VERSION 5.8 ;
BUSBITCHARS "[]" ;
DIVIDERCHAR "/" ;
CLEARANCEMEASURE EUCLIDEAN ;

SITE coresite_DH_P
    SIZE 0.0450 BY 0.2880 ;
    CLASS CORE ;
    SYMMETRY X Y ;
END coresite_DH_P

SITE coresite_DH_N
    SIZE 0.0450 BY 0.2880 ;
    CLASS CORE ;
    SYMMETRY X Y ;
END coresite_DH_N

SITE coresite
    SIZE 0.0450 BY 0.1440 ;
    CLASS CORE ;
    SYMMETRY X Y ;
END coresite

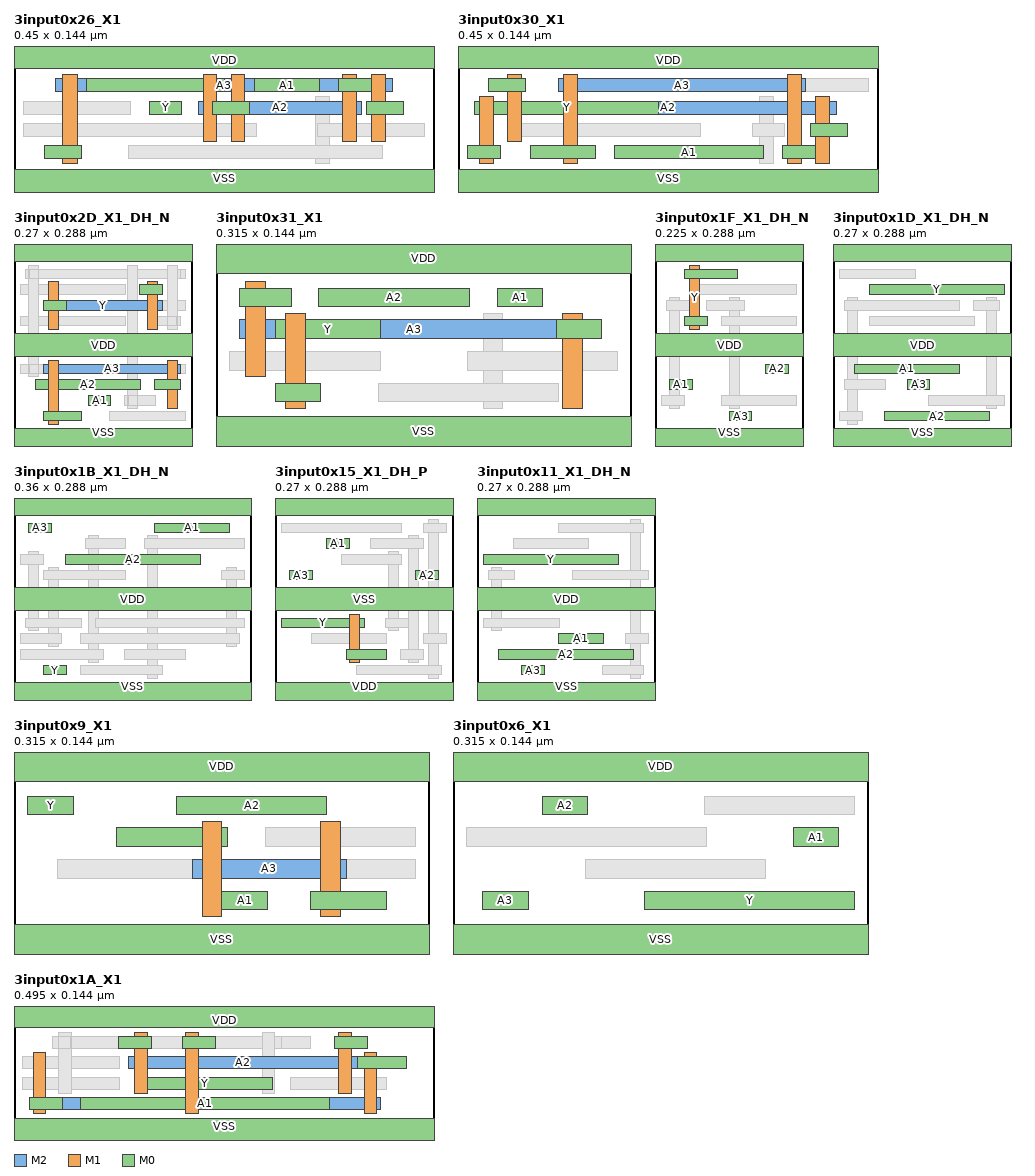
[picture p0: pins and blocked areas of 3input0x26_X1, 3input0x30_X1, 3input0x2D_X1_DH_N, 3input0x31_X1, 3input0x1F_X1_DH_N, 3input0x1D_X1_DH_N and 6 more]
MACRO 3input0x26_X1
  CLASS CORE ;
  ORIGIN 0 0 ;
  FOREIGN 3input0x26_X1 0 0 ;
  SIZE 0.4500 BY 0.1440 ;
  SYMMETRY X Y ;
  SITE coresite ;
  PIN A2
    DIRECTION INPUT ;
    USE SIGNAL ;
    PORT
      LAYER M2 ;
        RECT 0.1980 0.0910 0.3720 0.0770 ;
      LAYER M1 ;
        RECT 0.2025 0.1200 0.2175 0.0480 ;
        RECT 0.3525 0.1200 0.3675 0.0480 ;
      LAYER M0 ;
        RECT 0.0780 0.1150 0.2250 0.1010 ;
        RECT 0.3480 0.1150 0.3825 0.1010 ;
    END
  END A2
  PIN A3
    DIRECTION INPUT ;
    USE SIGNAL ;
    PORT
      LAYER M2 ;
        RECT 0.0450 0.1150 0.4050 0.1010 ;
      LAYER M1 ;
        RECT 0.0525 0.1200 0.0675 0.0240 ;
        RECT 0.2325 0.1200 0.2475 0.0480 ;
        RECT 0.3825 0.1200 0.3975 0.0480 ;
      LAYER M0 ;
        RECT 0.0330 0.0430 0.0720 0.0290 ;
        RECT 0.2130 0.0910 0.2520 0.0770 ;
        RECT 0.3780 0.0910 0.4170 0.0770 ;
    END
  END A3
  PIN Y
    DIRECTION OUTPUT ;
    USE SIGNAL ;
    PORT
      LAYER M0 ;
        RECT 0.1455 0.0910 0.1800 0.0770 ;
    END
  END Y
  PIN A1
    DIRECTION INPUT ;
    USE SIGNAL ;
    PORT
      LAYER M0 ;
        RECT 0.2580 0.1150 0.3270 0.1010 ;
    END
  END A1
  PIN VDD
    DIRECTION INOUT ;
    USE POWER ;
    SHAPE ABUTMENT ;
    PORT
      LAYER M0 ;
        RECT 0.0000 0.1260 0.4500 0.1620 ;
    END
  END VDD
  PIN VSS
    DIRECTION INOUT ;
    USE GROUND ;
    SHAPE ABUTMENT ;
    PORT
      LAYER M0 ;
        RECT 0.0000 -0.0180 0.4500 0.0180 ;
    END
  END VSS
  OBS
      LAYER V0 ;
        RECT 0.0530 0.0290 0.0670 0.0430 ;
        RECT 0.2330 0.0770 0.2470 0.0910 ;
        RECT 0.3830 0.0770 0.3970 0.0910 ;
        RECT 0.2030 0.1010 0.2170 0.1150 ;
        RECT 0.3530 0.1010 0.3670 0.1150 ;
        RECT 0.3230 0.0770 0.3370 0.0910 ;
        RECT 0.3230 0.0290 0.3370 0.0430 ;
      LAYER M1 ;
        RECT 0.3225 0.0960 0.3375 0.0240 ;
      LAYER M0 ;
        RECT 0.1230 0.0290 0.3945 0.0430 ;
        RECT 0.0105 0.0530 0.2595 0.0670 ;
        RECT 0.3255 0.0530 0.4395 0.0670 ;
        RECT 0.0105 0.0770 0.1245 0.0910 ;
        RECT 0.3150 0.0770 0.3495 0.0910 ;
      LAYER V1 ;
        RECT 0.0530 0.1010 0.0670 0.1150 ;
        RECT 0.2330 0.1010 0.2470 0.1150 ;
        RECT 0.3830 0.1010 0.3970 0.1150 ;
        RECT 0.2030 0.0770 0.2170 0.0910 ;
        RECT 0.3530 0.0770 0.3670 0.0910 ;
  END
END 3input0x26_X1

MACRO 3input0x30_X1
  CLASS CORE ;
  ORIGIN 0 0 ;
  FOREIGN 3input0x30_X1 0 0 ;
  SIZE 0.4500 BY 0.1440 ;
  SYMMETRY X Y ;
  SITE coresite ;
  PIN Y
    DIRECTION OUTPUT ;
    USE SIGNAL ;
    PORT
      LAYER M1 ;
        RECT 0.0225 0.0960 0.0375 0.0240 ;
      LAYER M0 ;
        RECT 0.0105 0.0430 0.0450 0.0290 ;
        RECT 0.0180 0.0910 0.2145 0.0770 ;
    END
  END Y
  PIN A2
    DIRECTION INPUT ;
    USE SIGNAL ;
    PORT
      LAYER M2 ;
        RECT 0.0450 0.0910 0.4050 0.0770 ;
      LAYER M1 ;
        RECT 0.3825 0.0960 0.3975 0.0240 ;
        RECT 0.0525 0.1200 0.0675 0.0480 ;
      LAYER M0 ;
        RECT 0.3780 0.0670 0.4170 0.0530 ;
        RECT 0.0330 0.1150 0.0720 0.1010 ;
    END
  END A2
  PIN A3
    DIRECTION INPUT ;
    USE SIGNAL ;
    PORT
      LAYER M2 ;
        RECT 0.1080 0.1150 0.3720 0.1010 ;
      LAYER M1 ;
        RECT 0.1125 0.1200 0.1275 0.0240 ;
        RECT 0.3525 0.1200 0.3675 0.0240 ;
      LAYER M0 ;
        RECT 0.0780 0.0430 0.1470 0.0290 ;
        RECT 0.3480 0.0430 0.3825 0.0290 ;
    END
  END A3
  PIN A1
    DIRECTION INPUT ;
    USE SIGNAL ;
    PORT
      LAYER M0 ;
        RECT 0.1680 0.0430 0.3270 0.0290 ;
    END
  END A1
  PIN VDD
    DIRECTION INOUT ;
    USE POWER ;
    SHAPE ABUTMENT ;
    PORT
      LAYER M0 ;
        RECT 0.0000 0.1260 0.4500 0.1620 ;
    END
  END VDD
  PIN VSS
    DIRECTION INOUT ;
    USE GROUND ;
    SHAPE ABUTMENT ;
    PORT
      LAYER M0 ;
        RECT 0.0000 -0.0180 0.4500 0.0180 ;
    END
  END VSS
  OBS
      LAYER V0 ;
        RECT 0.0530 0.1010 0.0670 0.1150 ;
        RECT 0.3830 0.0530 0.3970 0.0670 ;
        RECT 0.3230 0.0770 0.3370 0.0910 ;
        RECT 0.3230 0.0530 0.3370 0.0670 ;
        RECT 0.1130 0.0290 0.1270 0.0430 ;
        RECT 0.3530 0.0290 0.3670 0.0430 ;
        RECT 0.0230 0.0770 0.0370 0.0910 ;
        RECT 0.0230 0.0290 0.0370 0.0430 ;
      LAYER M1 ;
        RECT 0.3225 0.0960 0.3375 0.0240 ;
      LAYER M0 ;
        RECT 0.0555 0.0530 0.2595 0.0670 ;
        RECT 0.3150 0.0530 0.3495 0.0670 ;
        RECT 0.2580 0.0770 0.3945 0.0910 ;
        RECT 0.1455 0.1010 0.2595 0.1150 ;
        RECT 0.3255 0.1010 0.4395 0.1150 ;
      LAYER V1 ;
        RECT 0.0530 0.0770 0.0670 0.0910 ;
        RECT 0.3830 0.0770 0.3970 0.0910 ;
        RECT 0.1130 0.1010 0.1270 0.1150 ;
        RECT 0.3530 0.1010 0.3670 0.1150 ;
  END
END 3input0x30_X1

MACRO 3input0x2D_X1_DH_N
  CLASS CORE ;
  ORIGIN 0 0 ;
  FOREIGN 3input0x2D_X1_DH_N 0 0 ;
  SIZE 0.2700 BY 0.2880 ;
  SYMMETRY X Y ;
  SITE coresite_DH_N ;
  PIN A3
    DIRECTION INPUT ;
    USE SIGNAL ;
    PORT
      LAYER M2 ;
        RECT 0.0450 0.1150 0.2520 0.1010 ;
      LAYER M1 ;
        RECT 0.0525 0.1200 0.0675 0.0240 ;
        RECT 0.2325 0.1200 0.2475 0.0480 ;
      LAYER M0 ;
        RECT 0.0450 0.0430 0.1020 0.0290 ;
        RECT 0.2130 0.0910 0.2520 0.0770 ;
    END
  END A3
  PIN Y
    DIRECTION OUTPUT ;
    USE SIGNAL ;
    PORT
      LAYER M2 ;
        RECT 0.0450 0.2110 0.2250 0.1970 ;
      LAYER M1 ;
        RECT 0.0525 0.2400 0.0675 0.1680 ;
        RECT 0.2025 0.2400 0.2175 0.1680 ;
      LAYER M0 ;
        RECT 0.0450 0.2110 0.0795 0.1970 ;
        RECT 0.1905 0.2350 0.2250 0.2210 ;
    END
  END Y
  PIN A1
    DIRECTION INPUT ;
    USE SIGNAL ;
    PORT
      LAYER M0 ;
        RECT 0.1125 0.0670 0.1470 0.0530 ;
    END
  END A1
  PIN A2
    DIRECTION INPUT ;
    USE SIGNAL ;
    PORT
      LAYER M0 ;
        RECT 0.0330 0.0910 0.1920 0.0770 ;
    END
  END A2
  PIN VDD
    DIRECTION INOUT ;
    USE POWER ;
    SHAPE ABUTMENT ;
    PORT
      LAYER M0 ;
        RECT 0.0000 0.1260 0.2700 0.1620 ;
    END
  END VDD
  PIN VSS
    DIRECTION INOUT ;
    USE GROUND ;
    SHAPE ABUTMENT ;
    PORT
      LAYER M0 ;
        RECT 0.0000 -0.0180 0.2700 0.0180 ;
        RECT 0.0000 0.2700 0.2700 0.3060 ;
    END
  END VSS
  OBS
      LAYER V1 ;
        RECT 0.2330 0.2450 0.2470 0.2590 ;
        RECT 0.0230 0.2450 0.0370 0.2590 ;
        RECT 0.1730 0.2450 0.1870 0.2590 ;
        RECT 0.0530 0.1010 0.0670 0.1150 ;
        RECT 0.2330 0.1010 0.2470 0.1150 ;
        RECT 0.0530 0.1970 0.0670 0.2110 ;
        RECT 0.2030 0.1970 0.2170 0.2110 ;
      LAYER M0 ;
        RECT 0.1455 0.0290 0.2595 0.0430 ;
        RECT 0.1680 0.0530 0.2145 0.0670 ;
        RECT 0.0105 0.1010 0.0450 0.1150 ;
        RECT 0.1455 0.1010 0.2595 0.1150 ;
        RECT 0.0105 0.1730 0.1695 0.1870 ;
        RECT 0.2130 0.1730 0.2520 0.1870 ;
        RECT 0.1005 0.1970 0.2595 0.2110 ;
        RECT 0.0105 0.2210 0.1695 0.2350 ;
        RECT 0.0180 0.2450 0.0570 0.2590 ;
        RECT 0.1005 0.2450 0.2595 0.2590 ;
      LAYER M2 ;
        RECT 0.0180 0.2450 0.2520 0.2590 ;
      LAYER M1 ;
        RECT 0.0225 0.2640 0.0375 0.0960 ;
        RECT 0.1725 0.2640 0.1875 0.0480 ;
        RECT 0.2325 0.2640 0.2475 0.1680 ;
      LAYER V0 ;
        RECT 0.2330 0.1730 0.2470 0.1870 ;
        RECT 0.0230 0.1010 0.0370 0.1150 ;
        RECT 0.0230 0.2450 0.0370 0.2590 ;
        RECT 0.1730 0.0530 0.1870 0.0670 ;
        RECT 0.0530 0.0290 0.0670 0.0430 ;
        RECT 0.2330 0.0770 0.2470 0.0910 ;
        RECT 0.0530 0.1970 0.0670 0.2110 ;
        RECT 0.2030 0.2210 0.2170 0.2350 ;
  END
END 3input0x2D_X1_DH_N

MACRO 3input0x31_X1
  CLASS CORE ;
  ORIGIN 0 0 ;
  FOREIGN 3input0x31_X1 0 0 ;
  SIZE 0.3150 BY 0.1440 ;
  SYMMETRY X Y ;
  SITE coresite ;
  PIN Y
    DIRECTION OUTPUT ;
    USE SIGNAL ;
    PORT
      LAYER M1 ;
        RECT 0.0525 0.0960 0.0675 0.0240 ;
      LAYER M0 ;
        RECT 0.0450 0.0430 0.0795 0.0290 ;
        RECT 0.0450 0.0910 0.1245 0.0770 ;
    END
  END Y
  PIN A3
    DIRECTION INPUT ;
    USE SIGNAL ;
    PORT
      LAYER M2 ;
        RECT 0.0180 0.0910 0.2820 0.0770 ;
      LAYER M1 ;
        RECT 0.2625 0.0960 0.2775 0.0240 ;
        RECT 0.0225 0.1200 0.0375 0.0480 ;
      LAYER M0 ;
        RECT 0.2580 0.0910 0.2925 0.0770 ;
        RECT 0.0180 0.1150 0.0570 0.1010 ;
    END
  END A3
  PIN A2
    DIRECTION INPUT ;
    USE SIGNAL ;
    PORT
      LAYER M0 ;
        RECT 0.0780 0.1150 0.1920 0.1010 ;
    END
  END A2
  PIN A1
    DIRECTION INPUT ;
    USE SIGNAL ;
    PORT
      LAYER M0 ;
        RECT 0.2130 0.1150 0.2475 0.1010 ;
    END
  END A1
  PIN VDD
    DIRECTION INOUT ;
    USE POWER ;
    SHAPE ABUTMENT ;
    PORT
      LAYER M0 ;
        RECT 0.0000 0.1260 0.3150 0.1620 ;
    END
  END VDD
  PIN VSS
    DIRECTION INOUT ;
    USE GROUND ;
    SHAPE ABUTMENT ;
    PORT
      LAYER M0 ;
        RECT 0.0000 -0.0180 0.3150 0.0180 ;
    END
  END VSS
  OBS
      LAYER V0 ;
        RECT 0.0530 0.0770 0.0670 0.0910 ;
        RECT 0.0530 0.0290 0.0670 0.0430 ;
        RECT 0.2030 0.0770 0.2170 0.0910 ;
        RECT 0.2030 0.0290 0.2170 0.0430 ;
        RECT 0.0230 0.1010 0.0370 0.1150 ;
        RECT 0.2630 0.0770 0.2770 0.0910 ;
      LAYER M1 ;
        RECT 0.2025 0.0960 0.2175 0.0240 ;
      LAYER M0 ;
        RECT 0.1230 0.0290 0.2595 0.0430 ;
        RECT 0.0105 0.0530 0.1245 0.0670 ;
        RECT 0.1905 0.0530 0.3045 0.0670 ;
        RECT 0.1905 0.0770 0.2250 0.0910 ;
      LAYER V1 ;
        RECT 0.0230 0.0770 0.0370 0.0910 ;
        RECT 0.2630 0.0770 0.2770 0.0910 ;
  END
END 3input0x31_X1

MACRO 3input0x1F_X1_DH_N
  CLASS CORE ;
  ORIGIN 0 0 ;
  FOREIGN 3input0x1F_X1_DH_N 0 0 ;
  SIZE 0.2250 BY 0.2880 ;
  SYMMETRY X Y ;
  SITE coresite_DH_N ;
  PIN Y
    DIRECTION OUTPUT ;
    USE SIGNAL ;
    PORT
      LAYER M1 ;
        RECT 0.0525 0.2640 0.0675 0.1680 ;
      LAYER M0 ;
        RECT 0.0450 0.1870 0.0795 0.1730 ;
        RECT 0.0450 0.2590 0.1245 0.2450 ;
    END
  END Y
  PIN A3
    DIRECTION INPUT ;
    USE SIGNAL ;
    PORT
      LAYER M0 ;
        RECT 0.1125 0.0430 0.1470 0.0290 ;
    END
  END A3
  PIN A1
    DIRECTION INPUT ;
    USE SIGNAL ;
    PORT
      LAYER M0 ;
        RECT 0.0225 0.0910 0.0570 0.0770 ;
    END
  END A1
  PIN A2
    DIRECTION INPUT ;
    USE SIGNAL ;
    PORT
      LAYER M0 ;
        RECT 0.1680 0.1150 0.2025 0.1010 ;
    END
  END A2
  PIN VDD
    DIRECTION INOUT ;
    USE POWER ;
    SHAPE ABUTMENT ;
    PORT
      LAYER M0 ;
        RECT 0.0000 0.1260 0.2250 0.1620 ;
    END
  END VDD
  PIN VSS
    DIRECTION INOUT ;
    USE GROUND ;
    SHAPE ABUTMENT ;
    PORT
      LAYER M0 ;
        RECT 0.0000 -0.0180 0.2250 0.0180 ;
        RECT 0.0000 0.2700 0.2250 0.3060 ;
    END
  END VSS
  OBS
      LAYER V0 ;
        RECT 0.0230 0.0530 0.0370 0.0670 ;
        RECT 0.0230 0.1970 0.0370 0.2110 ;
        RECT 0.0530 0.2450 0.0670 0.2590 ;
        RECT 0.0530 0.1730 0.0670 0.1870 ;
        RECT 0.1130 0.0530 0.1270 0.0670 ;
        RECT 0.1130 0.1970 0.1270 0.2110 ;
      LAYER M1 ;
        RECT 0.0225 0.2160 0.0375 0.0480 ;
        RECT 0.1125 0.2160 0.1275 0.0480 ;
      LAYER M0 ;
        RECT 0.0105 0.0530 0.0450 0.0670 ;
        RECT 0.1005 0.0530 0.2145 0.0670 ;
        RECT 0.1005 0.1730 0.2145 0.1870 ;
        RECT 0.0180 0.1970 0.0570 0.2110 ;
        RECT 0.0780 0.1970 0.1350 0.2110 ;
        RECT 0.0555 0.2210 0.2145 0.2350 ;
  END
END 3input0x1F_X1_DH_N

MACRO 3input0x1D_X1_DH_N
  CLASS CORE ;
  ORIGIN 0 0 ;
  FOREIGN 3input0x1D_X1_DH_N 0 0 ;
  SIZE 0.2700 BY 0.2880 ;
  SYMMETRY X Y ;
  SITE coresite_DH_N ;
  PIN A2
    DIRECTION INPUT ;
    USE SIGNAL ;
    PORT
      LAYER M0 ;
        RECT 0.0780 0.0430 0.2370 0.0290 ;
    END
  END A2
  PIN A3
    DIRECTION INPUT ;
    USE SIGNAL ;
    PORT
      LAYER M0 ;
        RECT 0.1125 0.0910 0.1470 0.0770 ;
    END
  END A3
  PIN A1
    DIRECTION INPUT ;
    USE SIGNAL ;
    PORT
      LAYER M0 ;
        RECT 0.0330 0.1150 0.1920 0.1010 ;
    END
  END A1
  PIN Y
    DIRECTION OUTPUT ;
    USE SIGNAL ;
    PORT
      LAYER M0 ;
        RECT 0.0555 0.2350 0.2595 0.2210 ;
    END
  END Y
  PIN VDD
    DIRECTION INOUT ;
    USE POWER ;
    SHAPE ABUTMENT ;
    PORT
      LAYER M0 ;
        RECT 0.0000 0.1260 0.2700 0.1620 ;
    END
  END VDD
  PIN VSS
    DIRECTION INOUT ;
    USE GROUND ;
    SHAPE ABUTMENT ;
    PORT
      LAYER M0 ;
        RECT 0.0000 -0.0180 0.2700 0.0180 ;
        RECT 0.0000 0.2700 0.2700 0.3060 ;
    END
  END VSS
  OBS
      LAYER V0 ;
        RECT 0.2330 0.0530 0.2470 0.0670 ;
        RECT 0.2330 0.1970 0.2470 0.2110 ;
        RECT 0.0230 0.0770 0.0370 0.0910 ;
        RECT 0.0230 0.0290 0.0370 0.0430 ;
        RECT 0.0230 0.1970 0.0370 0.2110 ;
      LAYER M1 ;
        RECT 0.0225 0.2160 0.0375 0.0240 ;
        RECT 0.2325 0.2160 0.2475 0.0480 ;
      LAYER M0 ;
        RECT 0.0105 0.0290 0.0450 0.0430 ;
        RECT 0.1455 0.0530 0.2595 0.0670 ;
        RECT 0.0180 0.0770 0.0795 0.0910 ;
        RECT 0.0555 0.1730 0.2145 0.1870 ;
        RECT 0.0180 0.1970 0.1920 0.2110 ;
        RECT 0.2130 0.1970 0.2520 0.2110 ;
        RECT 0.0105 0.2450 0.1245 0.2590 ;
  END
END 3input0x1D_X1_DH_N

MACRO 3input0x1B_X1_DH_N
  CLASS CORE ;
  ORIGIN 0 0 ;
  FOREIGN 3input0x1B_X1_DH_N 0 0 ;
  SIZE 0.3600 BY 0.2880 ;
  SYMMETRY X Y ;
  SITE coresite_DH_N ;
  PIN Y
    DIRECTION OUTPUT ;
    USE SIGNAL ;
    PORT
      LAYER M0 ;
        RECT 0.0450 0.0430 0.0795 0.0290 ;
    END
  END Y
  PIN A2
    DIRECTION INPUT ;
    USE SIGNAL ;
    PORT
      LAYER M0 ;
        RECT 0.0780 0.2110 0.2820 0.1970 ;
    END
  END A2
  PIN A3
    DIRECTION INPUT ;
    USE SIGNAL ;
    PORT
      LAYER M0 ;
        RECT 0.0225 0.2590 0.0570 0.2450 ;
    END
  END A3
  PIN A1
    DIRECTION INPUT ;
    USE SIGNAL ;
    PORT
      LAYER M0 ;
        RECT 0.2130 0.2590 0.3270 0.2450 ;
    END
  END A1
  PIN VDD
    DIRECTION INOUT ;
    USE POWER ;
    SHAPE ABUTMENT ;
    PORT
      LAYER M0 ;
        RECT 0.0000 0.1260 0.3600 0.1620 ;
    END
  END VDD
  PIN VSS
    DIRECTION INOUT ;
    USE GROUND ;
    SHAPE ABUTMENT ;
    PORT
      LAYER M0 ;
        RECT 0.0000 -0.0180 0.3600 0.0180 ;
        RECT 0.0000 0.2700 0.3600 0.3060 ;
    END
  END VSS
  OBS
      LAYER V0 ;
        RECT 0.0230 0.1010 0.0370 0.1150 ;
        RECT 0.0230 0.1970 0.0370 0.2110 ;
        RECT 0.0530 0.0770 0.0670 0.0910 ;
        RECT 0.0530 0.1730 0.0670 0.1870 ;
        RECT 0.3230 0.0770 0.3370 0.0910 ;
        RECT 0.3230 0.1730 0.3370 0.1870 ;
        RECT 0.1130 0.0530 0.1270 0.0670 ;
        RECT 0.1130 0.2210 0.1270 0.2350 ;
        RECT 0.2030 0.0290 0.2170 0.0430 ;
        RECT 0.2030 0.2210 0.2170 0.2350 ;
      LAYER M1 ;
        RECT 0.0525 0.1920 0.0675 0.0720 ;
        RECT 0.3225 0.1920 0.3375 0.0720 ;
        RECT 0.0225 0.2160 0.0375 0.0960 ;
        RECT 0.1125 0.2400 0.1275 0.0480 ;
        RECT 0.2025 0.2400 0.2175 0.0240 ;
      LAYER M0 ;
        RECT 0.1005 0.0290 0.2250 0.0430 ;
        RECT 0.0105 0.0530 0.1350 0.0670 ;
        RECT 0.1680 0.0530 0.2595 0.0670 ;
        RECT 0.0105 0.0770 0.0720 0.0910 ;
        RECT 0.1005 0.0770 0.3420 0.0910 ;
        RECT 0.0180 0.1010 0.1020 0.1150 ;
        RECT 0.1230 0.1010 0.3495 0.1150 ;
        RECT 0.0450 0.1730 0.1695 0.1870 ;
        RECT 0.3150 0.1730 0.3495 0.1870 ;
        RECT 0.0105 0.1970 0.0450 0.2110 ;
        RECT 0.1080 0.2210 0.1695 0.2350 ;
        RECT 0.1980 0.2210 0.3495 0.2350 ;
  END
END 3input0x1B_X1_DH_N

MACRO 3input0x15_X1_DH_P
  CLASS CORE ;
  ORIGIN 0 0 ;
  FOREIGN 3input0x15_X1_DH_P 0 0 ;
  SIZE 0.2700 BY 0.2880 ;
  SYMMETRY X Y ;
  SITE coresite_DH_P ;
  PIN Y
    DIRECTION OUTPUT ;
    USE SIGNAL ;
    PORT
      LAYER M1 ;
        RECT 0.1125 0.1200 0.1275 0.0480 ;
      LAYER M0 ;
        RECT 0.1080 0.0670 0.1695 0.0530 ;
        RECT 0.0105 0.1150 0.1350 0.1010 ;
    END
  END Y
  PIN A3
    DIRECTION INPUT ;
    USE SIGNAL ;
    PORT
      LAYER M0 ;
        RECT 0.0225 0.1870 0.0570 0.1730 ;
    END
  END A3
  PIN A2
    DIRECTION INPUT ;
    USE SIGNAL ;
    PORT
      LAYER M0 ;
        RECT 0.2130 0.1870 0.2475 0.1730 ;
    END
  END A2
  PIN A1
    DIRECTION INPUT ;
    USE SIGNAL ;
    PORT
      LAYER M0 ;
        RECT 0.0780 0.2350 0.1125 0.2210 ;
    END
  END A1
  PIN VDD
    DIRECTION INOUT ;
    USE POWER ;
    SHAPE ABUTMENT ;
    PORT
      LAYER M0 ;
        RECT 0.0000 -0.0180 0.2700 0.0180 ;
        RECT 0.0000 0.2700 0.2700 0.3060 ;
    END
  END VDD
  PIN VSS
    DIRECTION INOUT ;
    USE GROUND ;
    SHAPE ABUTMENT ;
    PORT
      LAYER M0 ;
        RECT 0.0000 0.1260 0.2700 0.1620 ;
    END
  END VSS
  OBS
      LAYER V0 ;
        RECT 0.1130 0.1010 0.1270 0.1150 ;
        RECT 0.1130 0.0530 0.1270 0.0670 ;
        RECT 0.1730 0.1010 0.1870 0.1150 ;
        RECT 0.1730 0.1970 0.1870 0.2110 ;
        RECT 0.2330 0.0770 0.2470 0.0910 ;
        RECT 0.2330 0.0290 0.2470 0.0430 ;
        RECT 0.2330 0.2450 0.2470 0.2590 ;
        RECT 0.2030 0.0530 0.2170 0.0670 ;
        RECT 0.2030 0.2210 0.2170 0.2350 ;
      LAYER M1 ;
        RECT 0.1725 0.2160 0.1875 0.0960 ;
        RECT 0.2025 0.2400 0.2175 0.0480 ;
        RECT 0.2325 0.2640 0.2475 0.0240 ;
      LAYER M0 ;
        RECT 0.1230 0.0290 0.2520 0.0430 ;
        RECT 0.1905 0.0530 0.2250 0.0670 ;
        RECT 0.0555 0.0770 0.1695 0.0910 ;
        RECT 0.2250 0.0770 0.2595 0.0910 ;
        RECT 0.1680 0.1010 0.2025 0.1150 ;
        RECT 0.1005 0.1970 0.1920 0.2110 ;
        RECT 0.1455 0.2210 0.2250 0.2350 ;
        RECT 0.0105 0.2450 0.1920 0.2590 ;
        RECT 0.2250 0.2450 0.2595 0.2590 ;
  END
END 3input0x15_X1_DH_P

MACRO 3input0x11_X1_DH_N
  CLASS CORE ;
  ORIGIN 0 0 ;
  FOREIGN 3input0x11_X1_DH_N 0 0 ;
  SIZE 0.2700 BY 0.2880 ;
  SYMMETRY X Y ;
  SITE coresite_DH_N ;
  PIN A3
    DIRECTION INPUT ;
    USE SIGNAL ;
    PORT
      LAYER M0 ;
        RECT 0.0675 0.0430 0.1020 0.0290 ;
    END
  END A3
  PIN A2
    DIRECTION INPUT ;
    USE SIGNAL ;
    PORT
      LAYER M0 ;
        RECT 0.0330 0.0670 0.2370 0.0530 ;
    END
  END A2
  PIN A1
    DIRECTION INPUT ;
    USE SIGNAL ;
    PORT
      LAYER M0 ;
        RECT 0.1230 0.0910 0.1920 0.0770 ;
    END
  END A1
  PIN Y
    DIRECTION OUTPUT ;
    USE SIGNAL ;
    PORT
      LAYER M0 ;
        RECT 0.0105 0.2110 0.2145 0.1970 ;
    END
  END Y
  PIN VDD
    DIRECTION INOUT ;
    USE POWER ;
    SHAPE ABUTMENT ;
    PORT
      LAYER M0 ;
        RECT 0.0000 0.1260 0.2700 0.1620 ;
    END
  END VDD
  PIN VSS
    DIRECTION INOUT ;
    USE GROUND ;
    SHAPE ABUTMENT ;
    PORT
      LAYER M0 ;
        RECT 0.0000 -0.0180 0.2700 0.0180 ;
        RECT 0.0000 0.2700 0.2700 0.3060 ;
    END
  END VSS
  OBS
      LAYER V0 ;
        RECT 0.2330 0.0770 0.2470 0.0910 ;
        RECT 0.2330 0.0290 0.2470 0.0430 ;
        RECT 0.2330 0.2450 0.2470 0.2590 ;
        RECT 0.0230 0.1010 0.0370 0.1150 ;
        RECT 0.0230 0.1730 0.0370 0.1870 ;
      LAYER M1 ;
        RECT 0.0225 0.1920 0.0375 0.0960 ;
        RECT 0.2325 0.2640 0.2475 0.0240 ;
      LAYER M0 ;
        RECT 0.1905 0.0290 0.2520 0.0430 ;
        RECT 0.2250 0.0770 0.2595 0.0910 ;
        RECT 0.0105 0.1010 0.1245 0.1150 ;
        RECT 0.0180 0.1730 0.0570 0.1870 ;
        RECT 0.1455 0.1730 0.2595 0.1870 ;
        RECT 0.0555 0.2210 0.1695 0.2350 ;
        RECT 0.1230 0.2450 0.2520 0.2590 ;
  END
END 3input0x11_X1_DH_N

MACRO 3input0x9_X1
  CLASS CORE ;
  ORIGIN 0 0 ;
  FOREIGN 3input0x9_X1 0 0 ;
  SIZE 0.3150 BY 0.1440 ;
  SYMMETRY X Y ;
  SITE coresite ;
  PIN A3
    DIRECTION INPUT ;
    USE SIGNAL ;
    PORT
      LAYER M2 ;
        RECT 0.1350 0.0670 0.2520 0.0530 ;
      LAYER M1 ;
        RECT 0.1425 0.0960 0.1575 0.0240 ;
        RECT 0.2325 0.0960 0.2475 0.0240 ;
      LAYER M0 ;
        RECT 0.0780 0.0910 0.1620 0.0770 ;
        RECT 0.2250 0.0430 0.2820 0.0290 ;
    END
  END A3
  PIN A1
    DIRECTION INPUT ;
    USE SIGNAL ;
    PORT
      LAYER M0 ;
        RECT 0.1575 0.0430 0.1920 0.0290 ;
    END
  END A1
  PIN Y
    DIRECTION OUTPUT ;
    USE SIGNAL ;
    PORT
      LAYER M0 ;
        RECT 0.0105 0.1150 0.0450 0.1010 ;
    END
  END Y
  PIN A2
    DIRECTION INPUT ;
    USE SIGNAL ;
    PORT
      LAYER M0 ;
        RECT 0.1230 0.1150 0.2370 0.1010 ;
    END
  END A2
  PIN VDD
    DIRECTION INOUT ;
    USE POWER ;
    SHAPE ABUTMENT ;
    PORT
      LAYER M0 ;
        RECT 0.0000 0.1260 0.3150 0.1620 ;
    END
  END VDD
  PIN VSS
    DIRECTION INOUT ;
    USE GROUND ;
    SHAPE ABUTMENT ;
    PORT
      LAYER M0 ;
        RECT 0.0000 -0.0180 0.3150 0.0180 ;
    END
  END VSS
  OBS
      LAYER M0 ;
        RECT 0.0330 0.0530 0.1695 0.0670 ;
        RECT 0.1905 0.0530 0.3045 0.0670 ;
        RECT 0.1905 0.0770 0.3045 0.0910 ;
      LAYER V0 ;
        RECT 0.1430 0.0770 0.1570 0.0910 ;
        RECT 0.2330 0.0290 0.2470 0.0430 ;
      LAYER V1 ;
        RECT 0.1430 0.0530 0.1570 0.0670 ;
        RECT 0.2330 0.0530 0.2470 0.0670 ;
  END
END 3input0x9_X1

MACRO 3input0x6_X1
  CLASS CORE ;
  ORIGIN 0 0 ;
  FOREIGN 3input0x6_X1 0 0 ;
  SIZE 0.3150 BY 0.1440 ;
  SYMMETRY X Y ;
  SITE coresite ;
  PIN A3
    DIRECTION INPUT ;
    USE SIGNAL ;
    PORT
      LAYER M0 ;
        RECT 0.0225 0.0430 0.0570 0.0290 ;
    END
  END A3
  PIN Y
    DIRECTION OUTPUT ;
    USE SIGNAL ;
    PORT
      LAYER M0 ;
        RECT 0.1455 0.0430 0.3045 0.0290 ;
    END
  END Y
  PIN A1
    DIRECTION INPUT ;
    USE SIGNAL ;
    PORT
      LAYER M0 ;
        RECT 0.2580 0.0910 0.2925 0.0770 ;
    END
  END A1
  PIN A2
    DIRECTION INPUT ;
    USE SIGNAL ;
    PORT
      LAYER M0 ;
        RECT 0.0675 0.1150 0.1020 0.1010 ;
    END
  END A2
  PIN VDD
    DIRECTION INOUT ;
    USE POWER ;
    SHAPE ABUTMENT ;
    PORT
      LAYER M0 ;
        RECT 0.0000 0.1260 0.3150 0.1620 ;
    END
  END VDD
  PIN VSS
    DIRECTION INOUT ;
    USE GROUND ;
    SHAPE ABUTMENT ;
    PORT
      LAYER M0 ;
        RECT 0.0000 -0.0180 0.3150 0.0180 ;
    END
  END VSS
  OBS
      LAYER M0 ;
        RECT 0.1005 0.0530 0.2370 0.0670 ;
        RECT 0.0105 0.0770 0.1920 0.0910 ;
        RECT 0.1905 0.1010 0.3045 0.1150 ;
  END
END 3input0x6_X1

MACRO 3input0x1A_X1
  CLASS CORE ;
  ORIGIN 0 0 ;
  FOREIGN 3input0x1A_X1 0 0 ;
  SIZE 0.4950 BY 0.1440 ;
  SYMMETRY X Y ;
  SITE coresite ;
  PIN A3
    DIRECTION INPUT ;
    USE SIGNAL ;
    PORT
      LAYER M2 ;
        RECT 0.0180 0.0430 0.4320 0.0290 ;
      LAYER M1 ;
        RECT 0.0225 0.0960 0.0375 0.0240 ;
        RECT 0.4125 0.0960 0.4275 0.0240 ;
        RECT 0.2025 0.1200 0.2175 0.0240 ;
      LAYER M0 ;
        RECT 0.0180 0.0430 0.0570 0.0290 ;
        RECT 0.4050 0.0910 0.4620 0.0770 ;
        RECT 0.1980 0.1150 0.2370 0.1010 ;
    END
  END A3
  PIN A2
    DIRECTION INPUT ;
    USE SIGNAL ;
    PORT
      LAYER M2 ;
        RECT 0.1350 0.0910 0.4050 0.0770 ;
      LAYER M1 ;
        RECT 0.1425 0.1200 0.1575 0.0480 ;
        RECT 0.3825 0.1200 0.3975 0.0480 ;
      LAYER M0 ;
        RECT 0.1230 0.1150 0.1620 0.1010 ;
        RECT 0.3780 0.1150 0.4170 0.1010 ;
    END
  END A2
  PIN A1
    DIRECTION INPUT ;
    USE SIGNAL ;
    PORT
      LAYER M0 ;
        RECT 0.0780 0.0430 0.3720 0.0290 ;
    END
  END A1
  PIN Y
    DIRECTION OUTPUT ;
    USE SIGNAL ;
    PORT
      LAYER M0 ;
        RECT 0.1455 0.0670 0.3045 0.0530 ;
    END
  END Y
  PIN VDD
    DIRECTION INOUT ;
    USE POWER ;
    SHAPE ABUTMENT ;
    PORT
      LAYER M0 ;
        RECT 0.0000 0.1260 0.4950 0.1620 ;
    END
  END VDD
  PIN VSS
    DIRECTION INOUT ;
    USE GROUND ;
    SHAPE ABUTMENT ;
    PORT
      LAYER M0 ;
        RECT 0.0000 -0.0180 0.4950 0.0180 ;
    END
  END VSS
  OBS
      LAYER V1 ;
        RECT 0.0230 0.0290 0.0370 0.0430 ;
        RECT 0.2030 0.0290 0.2170 0.0430 ;
        RECT 0.4130 0.0290 0.4270 0.0430 ;
        RECT 0.1430 0.0770 0.1570 0.0910 ;
        RECT 0.3830 0.0770 0.3970 0.0910 ;
        RECT 0.0530 0.1010 0.0670 0.1150 ;
        RECT 0.2930 0.1010 0.3070 0.1150 ;
      LAYER M0 ;
        RECT 0.0105 0.0530 0.1245 0.0670 ;
        RECT 0.3255 0.0530 0.4395 0.0670 ;
        RECT 0.0105 0.0770 0.1245 0.0910 ;
        RECT 0.2355 0.0770 0.3150 0.0910 ;
        RECT 0.0450 0.1010 0.0795 0.1150 ;
        RECT 0.2580 0.1010 0.3495 0.1150 ;
      LAYER M2 ;
        RECT 0.0450 0.1010 0.3150 0.1150 ;
      LAYER M1 ;
        RECT 0.0525 0.1200 0.0675 0.0480 ;
        RECT 0.2925 0.1200 0.3075 0.0480 ;
      LAYER V0 ;
        RECT 0.0230 0.0290 0.0370 0.0430 ;
        RECT 0.2030 0.1010 0.2170 0.1150 ;
        RECT 0.4130 0.0770 0.4270 0.0910 ;
        RECT 0.1430 0.1010 0.1570 0.1150 ;
        RECT 0.3830 0.1010 0.3970 0.1150 ;
        RECT 0.0530 0.1010 0.0670 0.1150 ;
        RECT 0.2930 0.0770 0.3070 0.0910 ;
  END
END 3input0x1A_X1

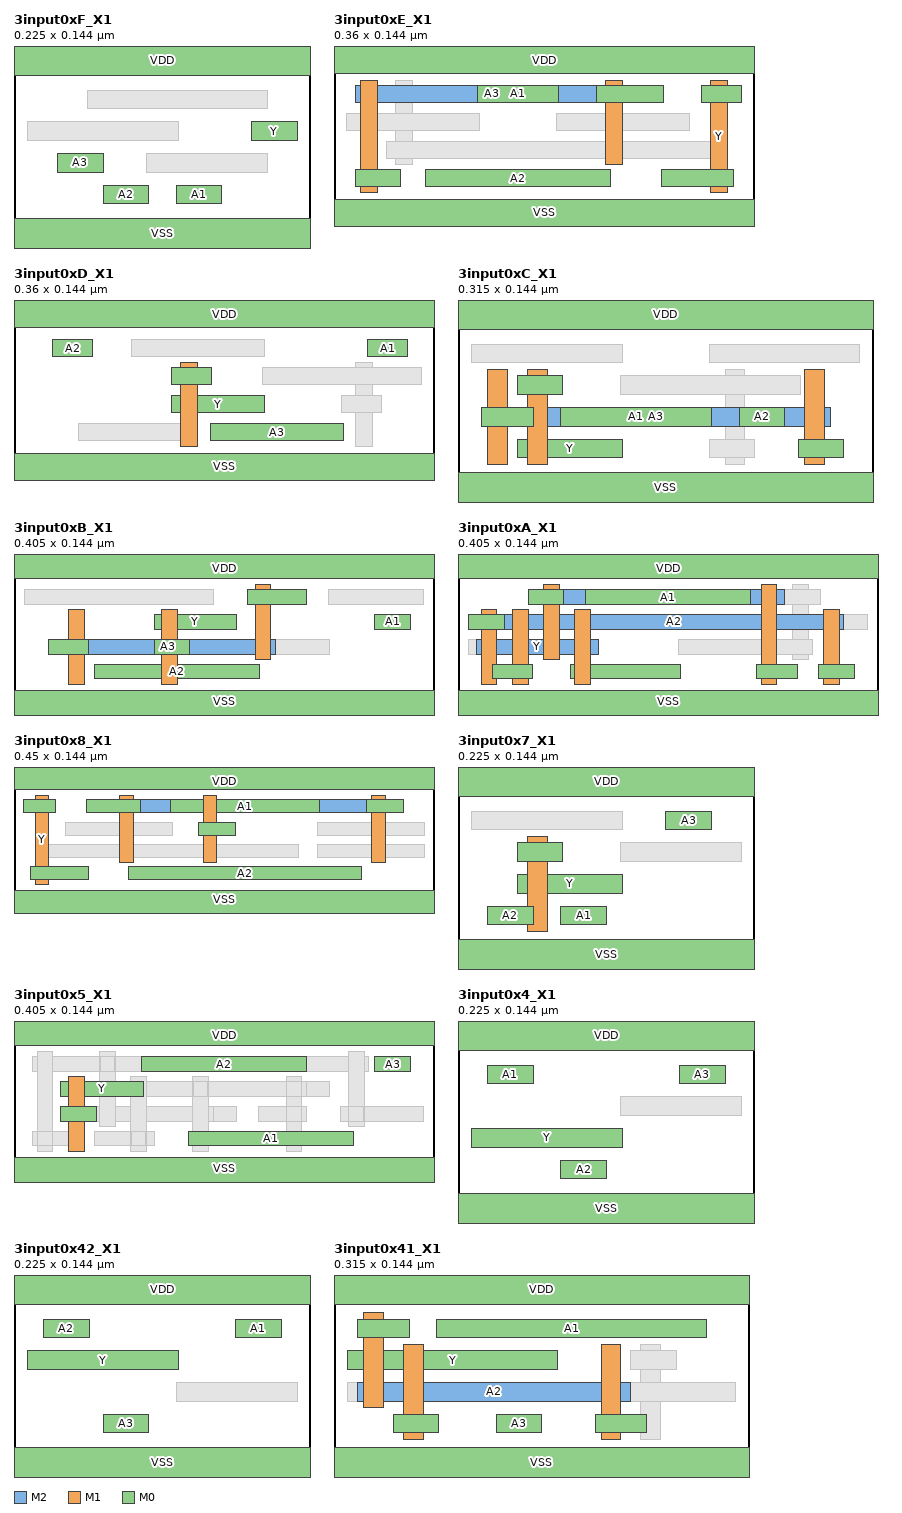
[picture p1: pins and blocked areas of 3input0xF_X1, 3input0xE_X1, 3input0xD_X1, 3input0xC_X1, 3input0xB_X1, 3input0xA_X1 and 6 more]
MACRO 3input0xF_X1
  CLASS CORE ;
  ORIGIN 0 0 ;
  FOREIGN 3input0xF_X1 0 0 ;
  SIZE 0.2250 BY 0.1440 ;
  SYMMETRY X Y ;
  SITE coresite ;
  PIN A2
    DIRECTION INPUT ;
    USE SIGNAL ;
    PORT
      LAYER M0 ;
        RECT 0.0675 0.0430 0.1020 0.0290 ;
    END
  END A2
  PIN A1
    DIRECTION INPUT ;
    USE SIGNAL ;
    PORT
      LAYER M0 ;
        RECT 0.1230 0.0430 0.1575 0.0290 ;
    END
  END A1
  PIN A3
    DIRECTION INPUT ;
    USE SIGNAL ;
    PORT
      LAYER M0 ;
        RECT 0.0330 0.0670 0.0675 0.0530 ;
    END
  END A3
  PIN Y
    DIRECTION OUTPUT ;
    USE SIGNAL ;
    PORT
      LAYER M0 ;
        RECT 0.1800 0.0910 0.2145 0.0770 ;
    END
  END Y
  PIN VDD
    DIRECTION INOUT ;
    USE POWER ;
    SHAPE ABUTMENT ;
    PORT
      LAYER M0 ;
        RECT 0.0000 0.1260 0.2250 0.1620 ;
    END
  END VDD
  PIN VSS
    DIRECTION INOUT ;
    USE GROUND ;
    SHAPE ABUTMENT ;
    PORT
      LAYER M0 ;
        RECT 0.0000 -0.0180 0.2250 0.0180 ;
    END
  END VSS
  OBS
      LAYER M0 ;
        RECT 0.1005 0.0530 0.1920 0.0670 ;
        RECT 0.0105 0.0770 0.1245 0.0910 ;
        RECT 0.0555 0.1010 0.1920 0.1150 ;
  END
END 3input0xF_X1

MACRO 3input0xE_X1
  CLASS CORE ;
  ORIGIN 0 0 ;
  FOREIGN 3input0xE_X1 0 0 ;
  SIZE 0.3600 BY 0.1440 ;
  SYMMETRY X Y ;
  SITE coresite ;
  PIN Y
    DIRECTION OUTPUT ;
    USE SIGNAL ;
    PORT
      LAYER M1 ;
        RECT 0.3225 0.1200 0.3375 0.0240 ;
      LAYER M0 ;
        RECT 0.2805 0.0430 0.3420 0.0290 ;
        RECT 0.3150 0.1150 0.3495 0.1010 ;
    END
  END Y
  PIN A3
    DIRECTION INPUT ;
    USE SIGNAL ;
    PORT
      LAYER M2 ;
        RECT 0.0180 0.1150 0.2520 0.1010 ;
      LAYER M1 ;
        RECT 0.0225 0.1200 0.0375 0.0240 ;
        RECT 0.2325 0.1200 0.2475 0.0480 ;
      LAYER M0 ;
        RECT 0.0180 0.0430 0.0570 0.0290 ;
        RECT 0.2250 0.1150 0.2820 0.1010 ;
    END
  END A3
  PIN A2
    DIRECTION INPUT ;
    USE SIGNAL ;
    PORT
      LAYER M0 ;
        RECT 0.0780 0.0430 0.2370 0.0290 ;
    END
  END A2
  PIN A1
    DIRECTION INPUT ;
    USE SIGNAL ;
    PORT
      LAYER M0 ;
        RECT 0.1230 0.1150 0.1920 0.1010 ;
    END
  END A1
  PIN VDD
    DIRECTION INOUT ;
    USE POWER ;
    SHAPE ABUTMENT ;
    PORT
      LAYER M0 ;
        RECT 0.0000 0.1260 0.3600 0.1620 ;
    END
  END VDD
  PIN VSS
    DIRECTION INOUT ;
    USE GROUND ;
    SHAPE ABUTMENT ;
    PORT
      LAYER M0 ;
        RECT 0.0000 -0.0180 0.3600 0.0180 ;
    END
  END VSS
  OBS
      LAYER V0 ;
        RECT 0.3230 0.1010 0.3370 0.1150 ;
        RECT 0.3230 0.0290 0.3370 0.0430 ;
        RECT 0.0230 0.0290 0.0370 0.0430 ;
        RECT 0.2330 0.1010 0.2470 0.1150 ;
        RECT 0.0530 0.1010 0.0670 0.1150 ;
        RECT 0.0530 0.0530 0.0670 0.0670 ;
      LAYER M1 ;
        RECT 0.0525 0.1200 0.0675 0.0480 ;
      LAYER M0 ;
        RECT 0.0450 0.0530 0.3270 0.0670 ;
        RECT 0.0105 0.0770 0.1245 0.0910 ;
        RECT 0.1905 0.0770 0.3045 0.0910 ;
        RECT 0.0450 0.1010 0.0795 0.1150 ;
      LAYER V1 ;
        RECT 0.0230 0.1010 0.0370 0.1150 ;
        RECT 0.2330 0.1010 0.2470 0.1150 ;
  END
END 3input0xE_X1

MACRO 3input0xD_X1
  CLASS CORE ;
  ORIGIN 0 0 ;
  FOREIGN 3input0xD_X1 0 0 ;
  SIZE 0.3600 BY 0.1440 ;
  SYMMETRY X Y ;
  SITE coresite ;
  PIN Y
    DIRECTION OUTPUT ;
    USE SIGNAL ;
    PORT
      LAYER M1 ;
        RECT 0.1425 0.0960 0.1575 0.0240 ;
      LAYER M0 ;
        RECT 0.1350 0.0670 0.2145 0.0530 ;
        RECT 0.1350 0.0910 0.1695 0.0770 ;
    END
  END Y
  PIN A3
    DIRECTION INPUT ;
    USE SIGNAL ;
    PORT
      LAYER M0 ;
        RECT 0.1680 0.0430 0.2820 0.0290 ;
    END
  END A3
  PIN A2
    DIRECTION INPUT ;
    USE SIGNAL ;
    PORT
      LAYER M0 ;
        RECT 0.0330 0.1150 0.0675 0.1010 ;
    END
  END A2
  PIN A1
    DIRECTION INPUT ;
    USE SIGNAL ;
    PORT
      LAYER M0 ;
        RECT 0.3030 0.1150 0.3375 0.1010 ;
    END
  END A1
  PIN VDD
    DIRECTION INOUT ;
    USE POWER ;
    SHAPE ABUTMENT ;
    PORT
      LAYER M0 ;
        RECT 0.0000 0.1260 0.3600 0.1620 ;
    END
  END VDD
  PIN VSS
    DIRECTION INOUT ;
    USE GROUND ;
    SHAPE ABUTMENT ;
    PORT
      LAYER M0 ;
        RECT 0.0000 -0.0180 0.3600 0.0180 ;
    END
  END VSS
  OBS
      LAYER V0 ;
        RECT 0.1430 0.0770 0.1570 0.0910 ;
        RECT 0.1430 0.0530 0.1570 0.0670 ;
        RECT 0.2930 0.0770 0.3070 0.0910 ;
        RECT 0.2930 0.0530 0.3070 0.0670 ;
      LAYER M1 ;
        RECT 0.2925 0.0960 0.3075 0.0240 ;
      LAYER M0 ;
        RECT 0.0555 0.0290 0.1470 0.0430 ;
        RECT 0.2805 0.0530 0.3150 0.0670 ;
        RECT 0.2130 0.0770 0.3495 0.0910 ;
        RECT 0.1005 0.1010 0.2145 0.1150 ;
  END
END 3input0xD_X1

MACRO 3input0xC_X1
  CLASS CORE ;
  ORIGIN 0 0 ;
  FOREIGN 3input0xC_X1 0 0 ;
  SIZE 0.3150 BY 0.1440 ;
  SYMMETRY X Y ;
  SITE coresite ;
  PIN Y
    DIRECTION OUTPUT ;
    USE SIGNAL ;
    PORT
      LAYER M1 ;
        RECT 0.0525 0.0960 0.0675 0.0240 ;
      LAYER M0 ;
        RECT 0.0450 0.0430 0.1245 0.0290 ;
        RECT 0.0450 0.0910 0.0795 0.0770 ;
    END
  END Y
  PIN A3
    DIRECTION INPUT ;
    USE SIGNAL ;
    PORT
      LAYER M2 ;
        RECT 0.0180 0.0670 0.2820 0.0530 ;
      LAYER M1 ;
        RECT 0.0225 0.0960 0.0375 0.0240 ;
        RECT 0.2625 0.0960 0.2775 0.0240 ;
      LAYER M0 ;
        RECT 0.0180 0.0670 0.0570 0.0530 ;
        RECT 0.2580 0.0430 0.2925 0.0290 ;
    END
  END A3
  PIN A1
    DIRECTION INPUT ;
    USE SIGNAL ;
    PORT
      LAYER M0 ;
        RECT 0.0780 0.0670 0.1920 0.0530 ;
    END
  END A1
  PIN A2
    DIRECTION INPUT ;
    USE SIGNAL ;
    PORT
      LAYER M0 ;
        RECT 0.2130 0.0670 0.2475 0.0530 ;
    END
  END A2
  PIN VDD
    DIRECTION INOUT ;
    USE POWER ;
    SHAPE ABUTMENT ;
    PORT
      LAYER M0 ;
        RECT 0.0000 0.1260 0.3150 0.1620 ;
    END
  END VDD
  PIN VSS
    DIRECTION INOUT ;
    USE GROUND ;
    SHAPE ABUTMENT ;
    PORT
      LAYER M0 ;
        RECT 0.0000 -0.0180 0.3150 0.0180 ;
    END
  END VSS
  OBS
      LAYER V0 ;
        RECT 0.0230 0.0530 0.0370 0.0670 ;
        RECT 0.2630 0.0290 0.2770 0.0430 ;
        RECT 0.2030 0.0770 0.2170 0.0910 ;
        RECT 0.2030 0.0290 0.2170 0.0430 ;
        RECT 0.0530 0.0770 0.0670 0.0910 ;
        RECT 0.0530 0.0290 0.0670 0.0430 ;
      LAYER M1 ;
        RECT 0.2025 0.0960 0.2175 0.0240 ;
      LAYER M0 ;
        RECT 0.1905 0.0290 0.2250 0.0430 ;
        RECT 0.1230 0.0770 0.2595 0.0910 ;
        RECT 0.0105 0.1010 0.1245 0.1150 ;
        RECT 0.1905 0.1010 0.3045 0.1150 ;
      LAYER V1 ;
        RECT 0.0230 0.0530 0.0370 0.0670 ;
        RECT 0.2630 0.0530 0.2770 0.0670 ;
  END
END 3input0xC_X1

MACRO 3input0xB_X1
  CLASS CORE ;
  ORIGIN 0 0 ;
  FOREIGN 3input0xB_X1 0 0 ;
  SIZE 0.4050 BY 0.1440 ;
  SYMMETRY X Y ;
  SITE coresite ;
  PIN Y
    DIRECTION OUTPUT ;
    USE SIGNAL ;
    PORT
      LAYER M1 ;
        RECT 0.1425 0.0960 0.1575 0.0240 ;
      LAYER M0 ;
        RECT 0.1350 0.0670 0.1695 0.0530 ;
        RECT 0.1350 0.0910 0.2145 0.0770 ;
    END
  END Y
  PIN A3
    DIRECTION INPUT ;
    USE SIGNAL ;
    PORT
      LAYER M2 ;
        RECT 0.0450 0.0670 0.2520 0.0530 ;
      LAYER M1 ;
        RECT 0.0525 0.0960 0.0675 0.0240 ;
        RECT 0.2325 0.1200 0.2475 0.0480 ;
      LAYER M0 ;
        RECT 0.0330 0.0670 0.0720 0.0530 ;
        RECT 0.2250 0.1150 0.2820 0.1010 ;
    END
  END A3
  PIN A2
    DIRECTION INPUT ;
    USE SIGNAL ;
    PORT
      LAYER M0 ;
        RECT 0.0780 0.0430 0.2370 0.0290 ;
    END
  END A2
  PIN A1
    DIRECTION INPUT ;
    USE SIGNAL ;
    PORT
      LAYER M0 ;
        RECT 0.3480 0.0910 0.3825 0.0770 ;
    END
  END A1
  PIN VDD
    DIRECTION INOUT ;
    USE POWER ;
    SHAPE ABUTMENT ;
    PORT
      LAYER M0 ;
        RECT 0.0000 0.1260 0.4050 0.1620 ;
    END
  END VDD
  PIN VSS
    DIRECTION INOUT ;
    USE GROUND ;
    SHAPE ABUTMENT ;
    PORT
      LAYER M0 ;
        RECT 0.0000 -0.0180 0.4050 0.0180 ;
    END
  END VSS
  OBS
      LAYER M0 ;
        RECT 0.1905 0.0530 0.3045 0.0670 ;
        RECT 0.0105 0.1010 0.1920 0.1150 ;
        RECT 0.3030 0.1010 0.3945 0.1150 ;
      LAYER V0 ;
        RECT 0.0530 0.0530 0.0670 0.0670 ;
        RECT 0.2330 0.1010 0.2470 0.1150 ;
        RECT 0.1430 0.0770 0.1570 0.0910 ;
        RECT 0.1430 0.0530 0.1570 0.0670 ;
      LAYER V1 ;
        RECT 0.0530 0.0530 0.0670 0.0670 ;
        RECT 0.2330 0.0530 0.2470 0.0670 ;
  END
END 3input0xB_X1

MACRO 3input0xA_X1
  CLASS CORE ;
  ORIGIN 0 0 ;
  FOREIGN 3input0xA_X1 0 0 ;
  SIZE 0.4050 BY 0.1440 ;
  SYMMETRY X Y ;
  SITE coresite ;
  PIN Y
    DIRECTION OUTPUT ;
    USE SIGNAL ;
    PORT
      LAYER M2 ;
        RECT 0.0180 0.0670 0.1350 0.0530 ;
      LAYER M1 ;
        RECT 0.0225 0.0960 0.0375 0.0240 ;
        RECT 0.1125 0.0960 0.1275 0.0240 ;
      LAYER M0 ;
        RECT 0.0105 0.0910 0.0450 0.0770 ;
        RECT 0.1080 0.0430 0.2145 0.0290 ;
    END
  END Y
  PIN A2
    DIRECTION INPUT ;
    USE SIGNAL ;
    PORT
      LAYER M2 ;
        RECT 0.0450 0.0910 0.3720 0.0770 ;
      LAYER M1 ;
        RECT 0.0525 0.0960 0.0675 0.0240 ;
        RECT 0.3525 0.0960 0.3675 0.0240 ;
      LAYER M0 ;
        RECT 0.0330 0.0430 0.0720 0.0290 ;
        RECT 0.3480 0.0430 0.3825 0.0290 ;
    END
  END A2
  PIN A3
    DIRECTION INPUT ;
    USE SIGNAL ;
    PORT
      LAYER M2 ;
        RECT 0.0780 0.1150 0.3150 0.1010 ;
      LAYER M1 ;
        RECT 0.0825 0.1200 0.0975 0.0480 ;
        RECT 0.2925 0.1200 0.3075 0.0240 ;
      LAYER M0 ;
        RECT 0.0675 0.1150 0.1020 0.1010 ;
        RECT 0.2880 0.0430 0.3270 0.0290 ;
    END
  END A3
  PIN A1
    DIRECTION INPUT ;
    USE SIGNAL ;
    PORT
      LAYER M0 ;
        RECT 0.1230 0.1150 0.2820 0.1010 ;
    END
  END A1
  PIN VDD
    DIRECTION INOUT ;
    USE POWER ;
    SHAPE ABUTMENT ;
    PORT
      LAYER M0 ;
        RECT 0.0000 0.1260 0.4050 0.1620 ;
    END
  END VDD
  PIN VSS
    DIRECTION INOUT ;
    USE GROUND ;
    SHAPE ABUTMENT ;
    PORT
      LAYER M0 ;
        RECT 0.0000 -0.0180 0.4050 0.0180 ;
    END
  END VSS
  OBS
      LAYER V0 ;
        RECT 0.3230 0.1010 0.3370 0.1150 ;
        RECT 0.3230 0.0530 0.3370 0.0670 ;
        RECT 0.0830 0.1010 0.0970 0.1150 ;
        RECT 0.2930 0.0290 0.3070 0.0430 ;
        RECT 0.0230 0.0770 0.0370 0.0910 ;
        RECT 0.1130 0.0290 0.1270 0.0430 ;
        RECT 0.0530 0.0290 0.0670 0.0430 ;
        RECT 0.3530 0.0290 0.3670 0.0430 ;
      LAYER M1 ;
        RECT 0.3225 0.1200 0.3375 0.0480 ;
      LAYER M0 ;
        RECT 0.0105 0.0530 0.1245 0.0670 ;
        RECT 0.2130 0.0530 0.3420 0.0670 ;
        RECT 0.1005 0.0770 0.2145 0.0910 ;
        RECT 0.2805 0.0770 0.3945 0.0910 ;
        RECT 0.3150 0.1010 0.3495 0.1150 ;
      LAYER V1 ;
        RECT 0.0830 0.1010 0.0970 0.1150 ;
        RECT 0.2930 0.1010 0.3070 0.1150 ;
        RECT 0.0230 0.0530 0.0370 0.0670 ;
        RECT 0.1130 0.0530 0.1270 0.0670 ;
        RECT 0.0530 0.0770 0.0670 0.0910 ;
        RECT 0.3530 0.0770 0.3670 0.0910 ;
  END
END 3input0xA_X1

MACRO 3input0x8_X1
  CLASS CORE ;
  ORIGIN 0 0 ;
  FOREIGN 3input0x8_X1 0 0 ;
  SIZE 0.4500 BY 0.1440 ;
  SYMMETRY X Y ;
  SITE coresite ;
  PIN Y
    DIRECTION OUTPUT ;
    USE SIGNAL ;
    PORT
      LAYER M1 ;
        RECT 0.0225 0.1200 0.0375 0.0240 ;
      LAYER M0 ;
        RECT 0.0180 0.0430 0.0795 0.0290 ;
        RECT 0.0105 0.1150 0.0450 0.1010 ;
    END
  END Y
  PIN A3
    DIRECTION INPUT ;
    USE SIGNAL ;
    PORT
      LAYER M2 ;
        RECT 0.1080 0.1150 0.4050 0.1010 ;
      LAYER M1 ;
        RECT 0.1125 0.1200 0.1275 0.0480 ;
        RECT 0.2025 0.1200 0.2175 0.0480 ;
        RECT 0.3825 0.1200 0.3975 0.0480 ;
      LAYER M0 ;
        RECT 0.0780 0.1150 0.1350 0.1010 ;
        RECT 0.1980 0.0910 0.2370 0.0770 ;
        RECT 0.3780 0.1150 0.4170 0.1010 ;
    END
  END A3
  PIN A2
    DIRECTION INPUT ;
    USE SIGNAL ;
    PORT
      LAYER M0 ;
        RECT 0.1230 0.0430 0.3720 0.0290 ;
    END
  END A2
  PIN A1
    DIRECTION INPUT ;
    USE SIGNAL ;
    PORT
      LAYER M0 ;
        RECT 0.1680 0.1150 0.3270 0.1010 ;
    END
  END A1
  PIN VDD
    DIRECTION INOUT ;
    USE POWER ;
    SHAPE ABUTMENT ;
    PORT
      LAYER M0 ;
        RECT 0.0000 0.1260 0.4500 0.1620 ;
    END
  END VDD
  PIN VSS
    DIRECTION INOUT ;
    USE GROUND ;
    SHAPE ABUTMENT ;
    PORT
      LAYER M0 ;
        RECT 0.0000 -0.0180 0.4500 0.0180 ;
    END
  END VSS
  OBS
      LAYER M0 ;
        RECT 0.0330 0.0530 0.3045 0.0670 ;
        RECT 0.3255 0.0530 0.4395 0.0670 ;
        RECT 0.0555 0.0770 0.1695 0.0910 ;
        RECT 0.3255 0.0770 0.4395 0.0910 ;
      LAYER V0 ;
        RECT 0.0230 0.1010 0.0370 0.1150 ;
        RECT 0.0230 0.0290 0.0370 0.0430 ;
        RECT 0.1130 0.1010 0.1270 0.1150 ;
        RECT 0.2030 0.0770 0.2170 0.0910 ;
        RECT 0.3830 0.1010 0.3970 0.1150 ;
      LAYER V1 ;
        RECT 0.1130 0.1010 0.1270 0.1150 ;
        RECT 0.2030 0.1010 0.2170 0.1150 ;
        RECT 0.3830 0.1010 0.3970 0.1150 ;
  END
END 3input0x8_X1

MACRO 3input0x7_X1
  CLASS CORE ;
  ORIGIN 0 0 ;
  FOREIGN 3input0x7_X1 0 0 ;
  SIZE 0.2250 BY 0.1440 ;
  SYMMETRY X Y ;
  SITE coresite ;
  PIN Y
    DIRECTION OUTPUT ;
    USE SIGNAL ;
    PORT
      LAYER M1 ;
        RECT 0.0525 0.0960 0.0675 0.0240 ;
      LAYER M0 ;
        RECT 0.0450 0.0670 0.1245 0.0530 ;
        RECT 0.0450 0.0910 0.0795 0.0770 ;
    END
  END Y
  PIN A2
    DIRECTION INPUT ;
    USE SIGNAL ;
    PORT
      LAYER M0 ;
        RECT 0.0225 0.0430 0.0570 0.0290 ;
    END
  END A2
  PIN A1
    DIRECTION INPUT ;
    USE SIGNAL ;
    PORT
      LAYER M0 ;
        RECT 0.0780 0.0430 0.1125 0.0290 ;
    END
  END A1
  PIN A3
    DIRECTION INPUT ;
    USE SIGNAL ;
    PORT
      LAYER M0 ;
        RECT 0.1575 0.1150 0.1920 0.1010 ;
    END
  END A3
  PIN VDD
    DIRECTION INOUT ;
    USE POWER ;
    SHAPE ABUTMENT ;
    PORT
      LAYER M0 ;
        RECT 0.0000 0.1260 0.2250 0.1620 ;
    END
  END VDD
  PIN VSS
    DIRECTION INOUT ;
    USE GROUND ;
    SHAPE ABUTMENT ;
    PORT
      LAYER M0 ;
        RECT 0.0000 -0.0180 0.2250 0.0180 ;
    END
  END VSS
  OBS
      LAYER M0 ;
        RECT 0.1230 0.0770 0.2145 0.0910 ;
        RECT 0.0105 0.1010 0.1245 0.1150 ;
      LAYER V0 ;
        RECT 0.0530 0.0770 0.0670 0.0910 ;
        RECT 0.0530 0.0530 0.0670 0.0670 ;
  END
END 3input0x7_X1

MACRO 3input0x5_X1
  CLASS CORE ;
  ORIGIN 0 0 ;
  FOREIGN 3input0x5_X1 0 0 ;
  SIZE 0.4050 BY 0.1440 ;
  SYMMETRY X Y ;
  SITE coresite ;
  PIN Y
    DIRECTION OUTPUT ;
    USE SIGNAL ;
    PORT
      LAYER M1 ;
        RECT 0.0525 0.0960 0.0675 0.0240 ;
      LAYER M0 ;
        RECT 0.0450 0.0670 0.0795 0.0530 ;
        RECT 0.0450 0.0910 0.1245 0.0770 ;
    END
  END Y
  PIN A1
    DIRECTION INPUT ;
    USE SIGNAL ;
    PORT
      LAYER M0 ;
        RECT 0.1680 0.0430 0.3270 0.0290 ;
    END
  END A1
  PIN A2
    DIRECTION INPUT ;
    USE SIGNAL ;
    PORT
      LAYER M0 ;
        RECT 0.1230 0.1150 0.2820 0.1010 ;
    END
  END A2
  PIN A3
    DIRECTION INPUT ;
    USE SIGNAL ;
    PORT
      LAYER M0 ;
        RECT 0.3480 0.1150 0.3825 0.1010 ;
    END
  END A3
  PIN VDD
    DIRECTION INOUT ;
    USE POWER ;
    SHAPE ABUTMENT ;
    PORT
      LAYER M0 ;
        RECT 0.0000 0.1260 0.4050 0.1620 ;
    END
  END VDD
  PIN VSS
    DIRECTION INOUT ;
    USE GROUND ;
    SHAPE ABUTMENT ;
    PORT
      LAYER M0 ;
        RECT 0.0000 -0.0180 0.4050 0.0180 ;
    END
  END VSS
  OBS
      LAYER V1 ;
        RECT 0.0230 0.1010 0.0370 0.1150 ;
        RECT 0.3230 0.1010 0.3370 0.1150 ;
        RECT 0.1130 0.0770 0.1270 0.0910 ;
        RECT 0.2630 0.0770 0.2770 0.0910 ;
        RECT 0.0830 0.0530 0.0970 0.0670 ;
        RECT 0.1730 0.0530 0.1870 0.0670 ;
      LAYER M0 ;
        RECT 0.0180 0.0290 0.0570 0.0430 ;
        RECT 0.0780 0.0290 0.1350 0.0430 ;
        RECT 0.1005 0.0530 0.2145 0.0670 ;
        RECT 0.2355 0.0530 0.2820 0.0670 ;
        RECT 0.3150 0.0530 0.3945 0.0670 ;
        RECT 0.1680 0.0770 0.2145 0.0910 ;
        RECT 0.2580 0.0770 0.3045 0.0910 ;
        RECT 0.0555 0.1010 0.1020 0.1150 ;
      LAYER M2 ;
        RECT 0.0780 0.0530 0.1920 0.0670 ;
        RECT 0.1080 0.0770 0.2820 0.0910 ;
        RECT 0.0180 0.1010 0.3420 0.1150 ;
      LAYER M1 ;
        RECT 0.1125 0.0960 0.1275 0.0240 ;
        RECT 0.1725 0.0960 0.1875 0.0240 ;
        RECT 0.2625 0.0960 0.2775 0.0240 ;
        RECT 0.0225 0.1200 0.0375 0.0240 ;
        RECT 0.0825 0.1200 0.0975 0.0480 ;
        RECT 0.3225 0.1200 0.3375 0.0480 ;
      LAYER V0 ;
        RECT 0.0530 0.0770 0.0670 0.0910 ;
        RECT 0.0530 0.0530 0.0670 0.0670 ;
        RECT 0.0230 0.0290 0.0370 0.0430 ;
        RECT 0.3230 0.0530 0.3370 0.0670 ;
        RECT 0.1130 0.0290 0.1270 0.0430 ;
        RECT 0.2630 0.0770 0.2770 0.0910 ;
        RECT 0.2630 0.0530 0.2770 0.0670 ;
        RECT 0.0830 0.1010 0.0970 0.1150 ;
        RECT 0.1730 0.0770 0.1870 0.0910 ;
  END
END 3input0x5_X1

MACRO 3input0x4_X1
  CLASS CORE ;
  ORIGIN 0 0 ;
  FOREIGN 3input0x4_X1 0 0 ;
  SIZE 0.2250 BY 0.1440 ;
  SYMMETRY X Y ;
  SITE coresite ;
  PIN A2
    DIRECTION INPUT ;
    USE SIGNAL ;
    PORT
      LAYER M0 ;
        RECT 0.0780 0.0430 0.1125 0.0290 ;
    END
  END A2
  PIN Y
    DIRECTION OUTPUT ;
    USE SIGNAL ;
    PORT
      LAYER M0 ;
        RECT 0.0105 0.0670 0.1245 0.0530 ;
    END
  END Y
  PIN A1
    DIRECTION INPUT ;
    USE SIGNAL ;
    PORT
      LAYER M0 ;
        RECT 0.0225 0.1150 0.0570 0.1010 ;
    END
  END A1
  PIN A3
    DIRECTION INPUT ;
    USE SIGNAL ;
    PORT
      LAYER M0 ;
        RECT 0.1680 0.1150 0.2025 0.1010 ;
    END
  END A3
  PIN VDD
    DIRECTION INOUT ;
    USE POWER ;
    SHAPE ABUTMENT ;
    PORT
      LAYER M0 ;
        RECT 0.0000 0.1260 0.2250 0.1620 ;
    END
  END VDD
  PIN VSS
    DIRECTION INOUT ;
    USE GROUND ;
    SHAPE ABUTMENT ;
    PORT
      LAYER M0 ;
        RECT 0.0000 -0.0180 0.2250 0.0180 ;
    END
  END VSS
  OBS
      LAYER M0 ;
        RECT 0.1230 0.0770 0.2145 0.0910 ;
  END
END 3input0x4_X1

MACRO 3input0x42_X1
  CLASS CORE ;
  ORIGIN 0 0 ;
  FOREIGN 3input0x42_X1 0 0 ;
  SIZE 0.2250 BY 0.1440 ;
  SYMMETRY X Y ;
  SITE coresite ;
  PIN A3
    DIRECTION INPUT ;
    USE SIGNAL ;
    PORT
      LAYER M0 ;
        RECT 0.0675 0.0430 0.1020 0.0290 ;
    END
  END A3
  PIN Y
    DIRECTION OUTPUT ;
    USE SIGNAL ;
    PORT
      LAYER M0 ;
        RECT 0.0105 0.0910 0.1245 0.0770 ;
    END
  END Y
  PIN A2
    DIRECTION INPUT ;
    USE SIGNAL ;
    PORT
      LAYER M0 ;
        RECT 0.0225 0.1150 0.0570 0.1010 ;
    END
  END A2
  PIN A1
    DIRECTION INPUT ;
    USE SIGNAL ;
    PORT
      LAYER M0 ;
        RECT 0.1680 0.1150 0.2025 0.1010 ;
    END
  END A1
  PIN VDD
    DIRECTION INOUT ;
    USE POWER ;
    SHAPE ABUTMENT ;
    PORT
      LAYER M0 ;
        RECT 0.0000 0.1260 0.2250 0.1620 ;
    END
  END VDD
  PIN VSS
    DIRECTION INOUT ;
    USE GROUND ;
    SHAPE ABUTMENT ;
    PORT
      LAYER M0 ;
        RECT 0.0000 -0.0180 0.2250 0.0180 ;
    END
  END VSS
  OBS
      LAYER M0 ;
        RECT 0.1230 0.0530 0.2145 0.0670 ;
  END
END 3input0x42_X1

MACRO 3input0x41_X1
  CLASS CORE ;
  ORIGIN 0 0 ;
  FOREIGN 3input0x41_X1 0 0 ;
  SIZE 0.3150 BY 0.1440 ;
  SYMMETRY X Y ;
  SITE coresite ;
  PIN Y
    DIRECTION OUTPUT ;
    USE SIGNAL ;
    PORT
      LAYER M1 ;
        RECT 0.0525 0.0960 0.0675 0.0240 ;
      LAYER M0 ;
        RECT 0.0450 0.0430 0.0795 0.0290 ;
        RECT 0.0105 0.0910 0.1695 0.0770 ;
    END
  END Y
  PIN A2
    DIRECTION INPUT ;
    USE SIGNAL ;
    PORT
      LAYER M2 ;
        RECT 0.0180 0.0670 0.2250 0.0530 ;
      LAYER M1 ;
        RECT 0.2025 0.0960 0.2175 0.0240 ;
        RECT 0.0225 0.1200 0.0375 0.0480 ;
      LAYER M0 ;
        RECT 0.1980 0.0430 0.2370 0.0290 ;
        RECT 0.0180 0.1150 0.0570 0.1010 ;
    END
  END A2
  PIN A3
    DIRECTION INPUT ;
    USE SIGNAL ;
    PORT
      LAYER M0 ;
        RECT 0.1230 0.0430 0.1575 0.0290 ;
    END
  END A3
  PIN A1
    DIRECTION INPUT ;
    USE SIGNAL ;
    PORT
      LAYER M0 ;
        RECT 0.0780 0.1150 0.2820 0.1010 ;
    END
  END A1
  PIN VDD
    DIRECTION INOUT ;
    USE POWER ;
    SHAPE ABUTMENT ;
    PORT
      LAYER M0 ;
        RECT 0.0000 0.1260 0.3150 0.1620 ;
    END
  END VDD
  PIN VSS
    DIRECTION INOUT ;
    USE GROUND ;
    SHAPE ABUTMENT ;
    PORT
      LAYER M0 ;
        RECT 0.0000 -0.0180 0.3150 0.0180 ;
    END
  END VSS
  OBS
      LAYER V0 ;
        RECT 0.0230 0.1010 0.0370 0.1150 ;
        RECT 0.2030 0.0290 0.2170 0.0430 ;
        RECT 0.2330 0.0770 0.2470 0.0910 ;
        RECT 0.2330 0.0530 0.2470 0.0670 ;
        RECT 0.0530 0.0770 0.0670 0.0910 ;
        RECT 0.0530 0.0290 0.0670 0.0430 ;
      LAYER M1 ;
        RECT 0.2325 0.0960 0.2475 0.0240 ;
      LAYER M0 ;
        RECT 0.0105 0.0530 0.1245 0.0670 ;
        RECT 0.1680 0.0530 0.3045 0.0670 ;
        RECT 0.2250 0.0770 0.2595 0.0910 ;
      LAYER V1 ;
        RECT 0.0230 0.0530 0.0370 0.0670 ;
        RECT 0.2030 0.0530 0.2170 0.0670 ;
  END
END 3input0x41_X1

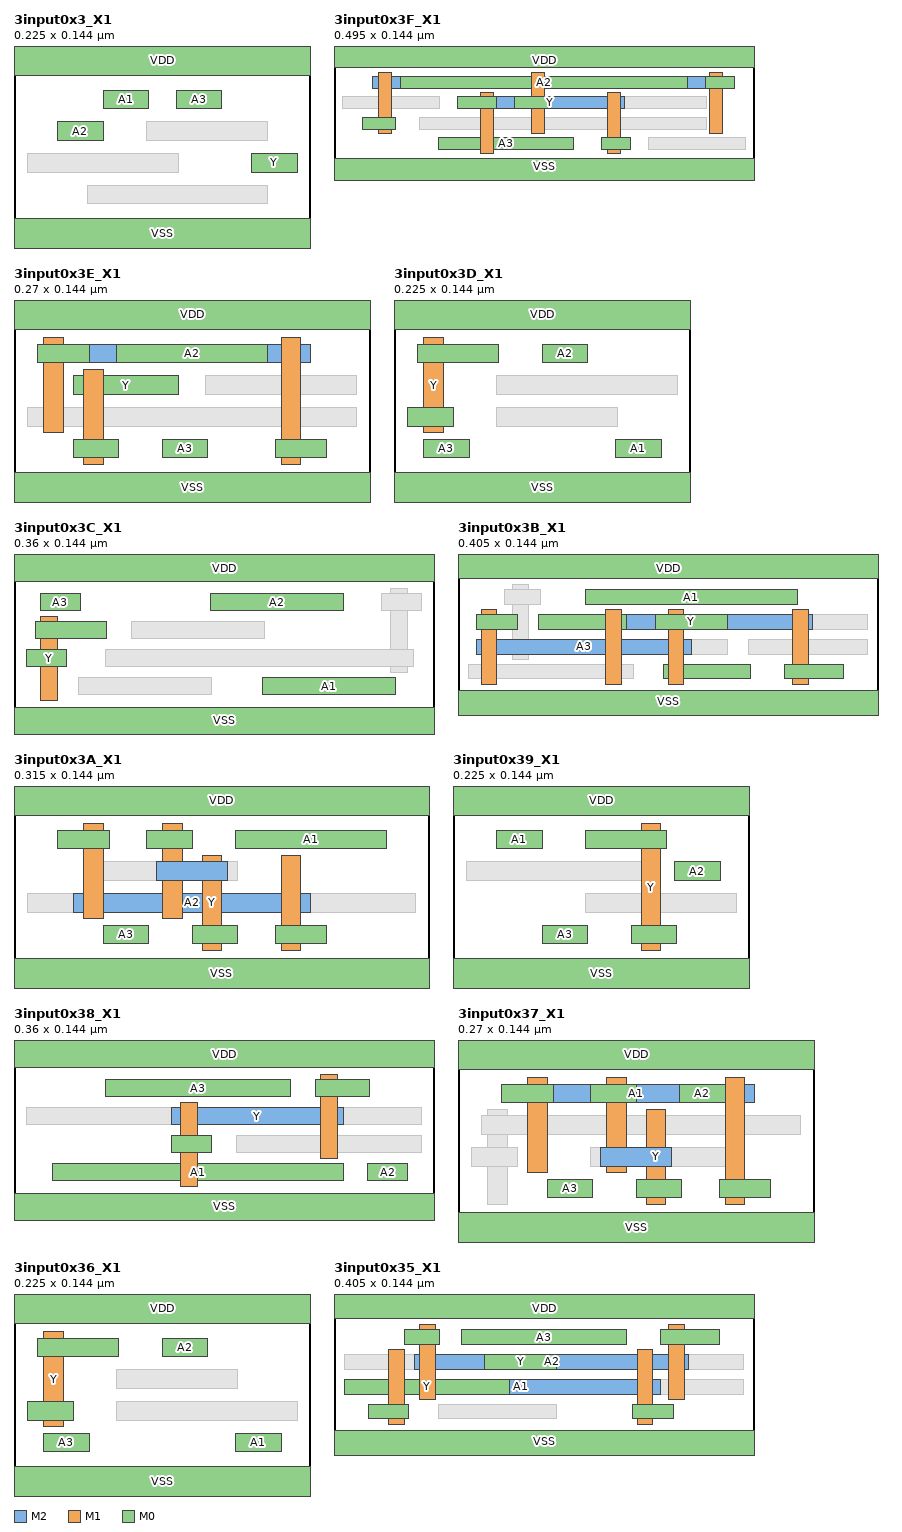
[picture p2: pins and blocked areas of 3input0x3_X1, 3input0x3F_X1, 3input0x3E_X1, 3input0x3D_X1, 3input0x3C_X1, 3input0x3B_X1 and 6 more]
MACRO 3input0x3_X1
  CLASS CORE ;
  ORIGIN 0 0 ;
  FOREIGN 3input0x3_X1 0 0 ;
  SIZE 0.2250 BY 0.1440 ;
  SYMMETRY X Y ;
  SITE coresite ;
  PIN Y
    DIRECTION OUTPUT ;
    USE SIGNAL ;
    PORT
      LAYER M0 ;
        RECT 0.1800 0.0670 0.2145 0.0530 ;
    END
  END Y
  PIN A2
    DIRECTION INPUT ;
    USE SIGNAL ;
    PORT
      LAYER M0 ;
        RECT 0.0330 0.0910 0.0675 0.0770 ;
    END
  END A2
  PIN A1
    DIRECTION INPUT ;
    USE SIGNAL ;
    PORT
      LAYER M0 ;
        RECT 0.0675 0.1150 0.1020 0.1010 ;
    END
  END A1
  PIN A3
    DIRECTION INPUT ;
    USE SIGNAL ;
    PORT
      LAYER M0 ;
        RECT 0.1230 0.1150 0.1575 0.1010 ;
    END
  END A3
  PIN VDD
    DIRECTION INOUT ;
    USE POWER ;
    SHAPE ABUTMENT ;
    PORT
      LAYER M0 ;
        RECT 0.0000 0.1260 0.2250 0.1620 ;
    END
  END VDD
  PIN VSS
    DIRECTION INOUT ;
    USE GROUND ;
    SHAPE ABUTMENT ;
    PORT
      LAYER M0 ;
        RECT 0.0000 -0.0180 0.2250 0.0180 ;
    END
  END VSS
  OBS
      LAYER M0 ;
        RECT 0.0555 0.0290 0.1920 0.0430 ;
        RECT 0.0105 0.0530 0.1245 0.0670 ;
        RECT 0.1005 0.0770 0.1920 0.0910 ;
  END
END 3input0x3_X1

MACRO 3input0x3F_X1
  CLASS CORE ;
  ORIGIN 0 0 ;
  FOREIGN 3input0x3F_X1 0 0 ;
  SIZE 0.4950 BY 0.1440 ;
  SYMMETRY X Y ;
  SITE coresite ;
  PIN Y
    DIRECTION OUTPUT ;
    USE SIGNAL ;
    PORT
      LAYER M2 ;
        RECT 0.1680 0.0910 0.3420 0.0770 ;
      LAYER M1 ;
        RECT 0.1725 0.0960 0.1875 0.0240 ;
        RECT 0.3225 0.0960 0.3375 0.0240 ;
      LAYER M0 ;
        RECT 0.1455 0.0910 0.1920 0.0770 ;
        RECT 0.3150 0.0430 0.3495 0.0290 ;
    END
  END Y
  PIN A1
    DIRECTION INPUT ;
    USE SIGNAL ;
    PORT
      LAYER M2 ;
        RECT 0.0450 0.1150 0.4620 0.1010 ;
      LAYER M1 ;
        RECT 0.0525 0.1200 0.0675 0.0480 ;
        RECT 0.2325 0.1200 0.2475 0.0480 ;
        RECT 0.4425 0.1200 0.4575 0.0480 ;
      LAYER M0 ;
        RECT 0.0330 0.0670 0.0720 0.0530 ;
        RECT 0.2130 0.0910 0.2520 0.0770 ;
        RECT 0.4380 0.1150 0.4725 0.1010 ;
    END
  END A1
  PIN A3
    DIRECTION INPUT ;
    USE SIGNAL ;
    PORT
      LAYER M0 ;
        RECT 0.1230 0.0430 0.2820 0.0290 ;
    END
  END A3
  PIN A2
    DIRECTION INPUT ;
    USE SIGNAL ;
    PORT
      LAYER M0 ;
        RECT 0.0780 0.1150 0.4170 0.1010 ;
    END
  END A2
  PIN VDD
    DIRECTION INOUT ;
    USE POWER ;
    SHAPE ABUTMENT ;
    PORT
      LAYER M0 ;
        RECT 0.0000 0.1260 0.4950 0.1620 ;
    END
  END VDD
  PIN VSS
    DIRECTION INOUT ;
    USE GROUND ;
    SHAPE ABUTMENT ;
    PORT
      LAYER M0 ;
        RECT 0.0000 -0.0180 0.4950 0.0180 ;
    END
  END VSS
  OBS
      LAYER M0 ;
        RECT 0.3705 0.0290 0.4845 0.0430 ;
        RECT 0.1005 0.0530 0.4395 0.0670 ;
        RECT 0.0105 0.0770 0.1245 0.0910 ;
        RECT 0.2805 0.0770 0.4395 0.0910 ;
      LAYER V0 ;
        RECT 0.0530 0.0530 0.0670 0.0670 ;
        RECT 0.2330 0.0770 0.2470 0.0910 ;
        RECT 0.4430 0.1010 0.4570 0.1150 ;
        RECT 0.1730 0.0770 0.1870 0.0910 ;
        RECT 0.3230 0.0290 0.3370 0.0430 ;
      LAYER V1 ;
        RECT 0.0530 0.1010 0.0670 0.1150 ;
        RECT 0.2330 0.1010 0.2470 0.1150 ;
        RECT 0.4430 0.1010 0.4570 0.1150 ;
        RECT 0.1730 0.0770 0.1870 0.0910 ;
        RECT 0.3230 0.0770 0.3370 0.0910 ;
  END
END 3input0x3F_X1

MACRO 3input0x3E_X1
  CLASS CORE ;
  ORIGIN 0 0 ;
  FOREIGN 3input0x3E_X1 0 0 ;
  SIZE 0.2700 BY 0.1440 ;
  SYMMETRY X Y ;
  SITE coresite ;
  PIN Y
    DIRECTION OUTPUT ;
    USE SIGNAL ;
    PORT
      LAYER M1 ;
        RECT 0.0525 0.0960 0.0675 0.0240 ;
      LAYER M0 ;
        RECT 0.0450 0.0430 0.0795 0.0290 ;
        RECT 0.0450 0.0910 0.1245 0.0770 ;
    END
  END Y
  PIN A1
    DIRECTION INPUT ;
    USE SIGNAL ;
    PORT
      LAYER M2 ;
        RECT 0.0180 0.1150 0.2250 0.1010 ;
      LAYER M1 ;
        RECT 0.0225 0.1200 0.0375 0.0480 ;
        RECT 0.2025 0.1200 0.2175 0.0240 ;
      LAYER M0 ;
        RECT 0.0180 0.1150 0.0570 0.1010 ;
        RECT 0.1980 0.0430 0.2370 0.0290 ;
    END
  END A1
  PIN A3
    DIRECTION INPUT ;
    USE SIGNAL ;
    PORT
      LAYER M0 ;
        RECT 0.1125 0.0430 0.1470 0.0290 ;
    END
  END A3
  PIN A2
    DIRECTION INPUT ;
    USE SIGNAL ;
    PORT
      LAYER M0 ;
        RECT 0.0780 0.1150 0.1920 0.1010 ;
    END
  END A2
  PIN VDD
    DIRECTION INOUT ;
    USE POWER ;
    SHAPE ABUTMENT ;
    PORT
      LAYER M0 ;
        RECT 0.0000 0.1260 0.2700 0.1620 ;
    END
  END VDD
  PIN VSS
    DIRECTION INOUT ;
    USE GROUND ;
    SHAPE ABUTMENT ;
    PORT
      LAYER M0 ;
        RECT 0.0000 -0.0180 0.2700 0.0180 ;
    END
  END VSS
  OBS
      LAYER M0 ;
        RECT 0.0105 0.0530 0.2595 0.0670 ;
        RECT 0.1455 0.0770 0.2595 0.0910 ;
      LAYER V0 ;
        RECT 0.0530 0.0770 0.0670 0.0910 ;
        RECT 0.0530 0.0290 0.0670 0.0430 ;
        RECT 0.0230 0.1010 0.0370 0.1150 ;
        RECT 0.2030 0.0290 0.2170 0.0430 ;
      LAYER V1 ;
        RECT 0.0230 0.1010 0.0370 0.1150 ;
        RECT 0.2030 0.1010 0.2170 0.1150 ;
  END
END 3input0x3E_X1

MACRO 3input0x3D_X1
  CLASS CORE ;
  ORIGIN 0 0 ;
  FOREIGN 3input0x3D_X1 0 0 ;
  SIZE 0.2250 BY 0.1440 ;
  SYMMETRY X Y ;
  SITE coresite ;
  PIN Y
    DIRECTION OUTPUT ;
    USE SIGNAL ;
    PORT
      LAYER M1 ;
        RECT 0.0225 0.1200 0.0375 0.0480 ;
      LAYER M0 ;
        RECT 0.0105 0.0670 0.0450 0.0530 ;
        RECT 0.0180 0.1150 0.0795 0.1010 ;
    END
  END Y
  PIN A3
    DIRECTION INPUT ;
    USE SIGNAL ;
    PORT
      LAYER M0 ;
        RECT 0.0225 0.0430 0.0570 0.0290 ;
    END
  END A3
  PIN A1
    DIRECTION INPUT ;
    USE SIGNAL ;
    PORT
      LAYER M0 ;
        RECT 0.1680 0.0430 0.2025 0.0290 ;
    END
  END A1
  PIN A2
    DIRECTION INPUT ;
    USE SIGNAL ;
    PORT
      LAYER M0 ;
        RECT 0.1125 0.1150 0.1470 0.1010 ;
    END
  END A2
  PIN VDD
    DIRECTION INOUT ;
    USE POWER ;
    SHAPE ABUTMENT ;
    PORT
      LAYER M0 ;
        RECT 0.0000 0.1260 0.2250 0.1620 ;
    END
  END VDD
  PIN VSS
    DIRECTION INOUT ;
    USE GROUND ;
    SHAPE ABUTMENT ;
    PORT
      LAYER M0 ;
        RECT 0.0000 -0.0180 0.2250 0.0180 ;
    END
  END VSS
  OBS
      LAYER M0 ;
        RECT 0.0780 0.0530 0.1695 0.0670 ;
        RECT 0.0780 0.0770 0.2145 0.0910 ;
      LAYER V0 ;
        RECT 0.0230 0.1010 0.0370 0.1150 ;
        RECT 0.0230 0.0530 0.0370 0.0670 ;
  END
END 3input0x3D_X1

MACRO 3input0x3C_X1
  CLASS CORE ;
  ORIGIN 0 0 ;
  FOREIGN 3input0x3C_X1 0 0 ;
  SIZE 0.3600 BY 0.1440 ;
  SYMMETRY X Y ;
  SITE coresite ;
  PIN Y
    DIRECTION OUTPUT ;
    USE SIGNAL ;
    PORT
      LAYER M1 ;
        RECT 0.0225 0.0960 0.0375 0.0240 ;
      LAYER M0 ;
        RECT 0.0105 0.0670 0.0450 0.0530 ;
        RECT 0.0180 0.0910 0.0795 0.0770 ;
    END
  END Y
  PIN A1
    DIRECTION INPUT ;
    USE SIGNAL ;
    PORT
      LAYER M0 ;
        RECT 0.2130 0.0430 0.3270 0.0290 ;
    END
  END A1
  PIN A3
    DIRECTION INPUT ;
    USE SIGNAL ;
    PORT
      LAYER M0 ;
        RECT 0.0225 0.1150 0.0570 0.1010 ;
    END
  END A3
  PIN A2
    DIRECTION INPUT ;
    USE SIGNAL ;
    PORT
      LAYER M0 ;
        RECT 0.1680 0.1150 0.2820 0.1010 ;
    END
  END A2
  PIN VDD
    DIRECTION INOUT ;
    USE POWER ;
    SHAPE ABUTMENT ;
    PORT
      LAYER M0 ;
        RECT 0.0000 0.1260 0.3600 0.1620 ;
    END
  END VDD
  PIN VSS
    DIRECTION INOUT ;
    USE GROUND ;
    SHAPE ABUTMENT ;
    PORT
      LAYER M0 ;
        RECT 0.0000 -0.0180 0.3600 0.0180 ;
    END
  END VSS
  OBS
      LAYER V0 ;
        RECT 0.0230 0.0770 0.0370 0.0910 ;
        RECT 0.0230 0.0530 0.0370 0.0670 ;
        RECT 0.3230 0.1010 0.3370 0.1150 ;
        RECT 0.3230 0.0530 0.3370 0.0670 ;
      LAYER M1 ;
        RECT 0.3225 0.1200 0.3375 0.0480 ;
      LAYER M0 ;
        RECT 0.0555 0.0290 0.1695 0.0430 ;
        RECT 0.0780 0.0530 0.3420 0.0670 ;
        RECT 0.1005 0.0770 0.2145 0.0910 ;
        RECT 0.3150 0.1010 0.3495 0.1150 ;
  END
END 3input0x3C_X1

MACRO 3input0x3B_X1
  CLASS CORE ;
  ORIGIN 0 0 ;
  FOREIGN 3input0x3B_X1 0 0 ;
  SIZE 0.4050 BY 0.1440 ;
  SYMMETRY X Y ;
  SITE coresite ;
  PIN A3
    DIRECTION INPUT ;
    USE SIGNAL ;
    PORT
      LAYER M2 ;
        RECT 0.0180 0.0670 0.2250 0.0530 ;
      LAYER M1 ;
        RECT 0.0225 0.0960 0.0375 0.0240 ;
        RECT 0.2025 0.0960 0.2175 0.0240 ;
      LAYER M0 ;
        RECT 0.0180 0.0910 0.0570 0.0770 ;
        RECT 0.1980 0.0430 0.2820 0.0290 ;
    END
  END A3
  PIN A2
    DIRECTION INPUT ;
    USE SIGNAL ;
    PORT
      LAYER M2 ;
        RECT 0.1350 0.0910 0.3420 0.0770 ;
      LAYER M1 ;
        RECT 0.1425 0.0960 0.1575 0.0240 ;
        RECT 0.3225 0.0960 0.3375 0.0240 ;
      LAYER M0 ;
        RECT 0.0780 0.0910 0.1620 0.0770 ;
        RECT 0.3150 0.0430 0.3720 0.0290 ;
    END
  END A2
  PIN Y
    DIRECTION OUTPUT ;
    USE SIGNAL ;
    PORT
      LAYER M0 ;
        RECT 0.1905 0.0910 0.2595 0.0770 ;
    END
  END Y
  PIN A1
    DIRECTION INPUT ;
    USE SIGNAL ;
    PORT
      LAYER M0 ;
        RECT 0.1230 0.1150 0.3270 0.1010 ;
    END
  END A1
  PIN VDD
    DIRECTION INOUT ;
    USE POWER ;
    SHAPE ABUTMENT ;
    PORT
      LAYER M0 ;
        RECT 0.0000 0.1260 0.4050 0.1620 ;
    END
  END VDD
  PIN VSS
    DIRECTION INOUT ;
    USE GROUND ;
    SHAPE ABUTMENT ;
    PORT
      LAYER M0 ;
        RECT 0.0000 -0.0180 0.4050 0.0180 ;
    END
  END VSS
  OBS
      LAYER V0 ;
        RECT 0.1430 0.0770 0.1570 0.0910 ;
        RECT 0.3230 0.0290 0.3370 0.0430 ;
        RECT 0.0230 0.0770 0.0370 0.0910 ;
        RECT 0.2030 0.0290 0.2170 0.0430 ;
        RECT 0.0530 0.1010 0.0670 0.1150 ;
        RECT 0.0530 0.0530 0.0670 0.0670 ;
      LAYER M1 ;
        RECT 0.0525 0.1200 0.0675 0.0480 ;
      LAYER M0 ;
        RECT 0.0105 0.0290 0.1695 0.0430 ;
        RECT 0.0450 0.0530 0.2595 0.0670 ;
        RECT 0.2805 0.0530 0.3945 0.0670 ;
        RECT 0.2805 0.0770 0.3945 0.0910 ;
        RECT 0.0450 0.1010 0.0795 0.1150 ;
      LAYER V1 ;
        RECT 0.1430 0.0770 0.1570 0.0910 ;
        RECT 0.3230 0.0770 0.3370 0.0910 ;
        RECT 0.0230 0.0530 0.0370 0.0670 ;
        RECT 0.2030 0.0530 0.2170 0.0670 ;
  END
END 3input0x3B_X1

MACRO 3input0x3A_X1
  CLASS CORE ;
  ORIGIN 0 0 ;
  FOREIGN 3input0x3A_X1 0 0 ;
  SIZE 0.3150 BY 0.1440 ;
  SYMMETRY X Y ;
  SITE coresite ;
  PIN A2
    DIRECTION INPUT ;
    USE SIGNAL ;
    PORT
      LAYER M2 ;
        RECT 0.0450 0.0670 0.2250 0.0530 ;
      LAYER M1 ;
        RECT 0.2025 0.0960 0.2175 0.0240 ;
        RECT 0.0525 0.1200 0.0675 0.0480 ;
      LAYER M0 ;
        RECT 0.1980 0.0430 0.2370 0.0290 ;
        RECT 0.0330 0.1150 0.0720 0.1010 ;
    END
  END A2
  PIN Y
    DIRECTION OUTPUT ;
    USE SIGNAL ;
    PORT
      LAYER M2 ;
        RECT 0.1080 0.0910 0.1620 0.0770 ;
      LAYER M1 ;
        RECT 0.1425 0.0960 0.1575 0.0240 ;
        RECT 0.1125 0.1200 0.1275 0.0480 ;
      LAYER M0 ;
        RECT 0.1350 0.0430 0.1695 0.0290 ;
        RECT 0.1005 0.1150 0.1350 0.1010 ;
    END
  END Y
  PIN A3
    DIRECTION INPUT ;
    USE SIGNAL ;
    PORT
      LAYER M0 ;
        RECT 0.0675 0.0430 0.1020 0.0290 ;
    END
  END A3
  PIN A1
    DIRECTION INPUT ;
    USE SIGNAL ;
    PORT
      LAYER M0 ;
        RECT 0.1680 0.1150 0.2820 0.1010 ;
    END
  END A1
  PIN VDD
    DIRECTION INOUT ;
    USE POWER ;
    SHAPE ABUTMENT ;
    PORT
      LAYER M0 ;
        RECT 0.0000 0.1260 0.3150 0.1620 ;
    END
  END VDD
  PIN VSS
    DIRECTION INOUT ;
    USE GROUND ;
    SHAPE ABUTMENT ;
    PORT
      LAYER M0 ;
        RECT 0.0000 -0.0180 0.3150 0.0180 ;
    END
  END VSS
  OBS
      LAYER M0 ;
        RECT 0.0105 0.0530 0.3045 0.0670 ;
        RECT 0.0555 0.0770 0.1695 0.0910 ;
      LAYER V0 ;
        RECT 0.1130 0.1010 0.1270 0.1150 ;
        RECT 0.1430 0.0290 0.1570 0.0430 ;
        RECT 0.0530 0.1010 0.0670 0.1150 ;
        RECT 0.2030 0.0290 0.2170 0.0430 ;
      LAYER V1 ;
        RECT 0.1130 0.0770 0.1270 0.0910 ;
        RECT 0.1430 0.0770 0.1570 0.0910 ;
        RECT 0.0530 0.0530 0.0670 0.0670 ;
        RECT 0.2030 0.0530 0.2170 0.0670 ;
  END
END 3input0x3A_X1

MACRO 3input0x39_X1
  CLASS CORE ;
  ORIGIN 0 0 ;
  FOREIGN 3input0x39_X1 0 0 ;
  SIZE 0.2250 BY 0.1440 ;
  SYMMETRY X Y ;
  SITE coresite ;
  PIN Y
    DIRECTION OUTPUT ;
    USE SIGNAL ;
    PORT
      LAYER M1 ;
        RECT 0.1425 0.1200 0.1575 0.0240 ;
      LAYER M0 ;
        RECT 0.1350 0.0430 0.1695 0.0290 ;
        RECT 0.1005 0.1150 0.1620 0.1010 ;
    END
  END Y
  PIN A3
    DIRECTION INPUT ;
    USE SIGNAL ;
    PORT
      LAYER M0 ;
        RECT 0.0675 0.0430 0.1020 0.0290 ;
    END
  END A3
  PIN A2
    DIRECTION INPUT ;
    USE SIGNAL ;
    PORT
      LAYER M0 ;
        RECT 0.1680 0.0910 0.2025 0.0770 ;
    END
  END A2
  PIN A1
    DIRECTION INPUT ;
    USE SIGNAL ;
    PORT
      LAYER M0 ;
        RECT 0.0330 0.1150 0.0675 0.1010 ;
    END
  END A1
  PIN VDD
    DIRECTION INOUT ;
    USE POWER ;
    SHAPE ABUTMENT ;
    PORT
      LAYER M0 ;
        RECT 0.0000 0.1260 0.2250 0.1620 ;
    END
  END VDD
  PIN VSS
    DIRECTION INOUT ;
    USE GROUND ;
    SHAPE ABUTMENT ;
    PORT
      LAYER M0 ;
        RECT 0.0000 -0.0180 0.2250 0.0180 ;
    END
  END VSS
  OBS
      LAYER M0 ;
        RECT 0.1005 0.0530 0.2145 0.0670 ;
        RECT 0.0105 0.0770 0.1470 0.0910 ;
      LAYER V0 ;
        RECT 0.1430 0.1010 0.1570 0.1150 ;
        RECT 0.1430 0.0290 0.1570 0.0430 ;
  END
END 3input0x39_X1

MACRO 3input0x38_X1
  CLASS CORE ;
  ORIGIN 0 0 ;
  FOREIGN 3input0x38_X1 0 0 ;
  SIZE 0.3600 BY 0.1440 ;
  SYMMETRY X Y ;
  SITE coresite ;
  PIN Y
    DIRECTION OUTPUT ;
    USE SIGNAL ;
    PORT
      LAYER M2 ;
        RECT 0.1350 0.0910 0.2820 0.0770 ;
      LAYER M1 ;
        RECT 0.1425 0.0960 0.1575 0.0240 ;
        RECT 0.2625 0.1200 0.2775 0.0480 ;
      LAYER M0 ;
        RECT 0.1350 0.0670 0.1695 0.0530 ;
        RECT 0.2580 0.1150 0.3045 0.1010 ;
    END
  END Y
  PIN A1
    DIRECTION INPUT ;
    USE SIGNAL ;
    PORT
      LAYER M0 ;
        RECT 0.0330 0.0430 0.2820 0.0290 ;
    END
  END A1
  PIN A2
    DIRECTION INPUT ;
    USE SIGNAL ;
    PORT
      LAYER M0 ;
        RECT 0.3030 0.0430 0.3375 0.0290 ;
    END
  END A2
  PIN A3
    DIRECTION INPUT ;
    USE SIGNAL ;
    PORT
      LAYER M0 ;
        RECT 0.0780 0.1150 0.2370 0.1010 ;
    END
  END A3
  PIN VDD
    DIRECTION INOUT ;
    USE POWER ;
    SHAPE ABUTMENT ;
    PORT
      LAYER M0 ;
        RECT 0.0000 0.1260 0.3600 0.1620 ;
    END
  END VDD
  PIN VSS
    DIRECTION INOUT ;
    USE GROUND ;
    SHAPE ABUTMENT ;
    PORT
      LAYER M0 ;
        RECT 0.0000 -0.0180 0.3600 0.0180 ;
    END
  END VSS
  OBS
      LAYER M0 ;
        RECT 0.1905 0.0530 0.3495 0.0670 ;
        RECT 0.0105 0.0770 0.1920 0.0910 ;
        RECT 0.2355 0.0770 0.3495 0.0910 ;
      LAYER V0 ;
        RECT 0.1430 0.0530 0.1570 0.0670 ;
        RECT 0.2630 0.1010 0.2770 0.1150 ;
      LAYER V1 ;
        RECT 0.1430 0.0770 0.1570 0.0910 ;
        RECT 0.2630 0.0770 0.2770 0.0910 ;
  END
END 3input0x38_X1

MACRO 3input0x37_X1
  CLASS CORE ;
  ORIGIN 0 0 ;
  FOREIGN 3input0x37_X1 0 0 ;
  SIZE 0.2700 BY 0.1440 ;
  SYMMETRY X Y ;
  SITE coresite ;
  PIN Y
    DIRECTION OUTPUT ;
    USE SIGNAL ;
    PORT
      LAYER M2 ;
        RECT 0.1080 0.0670 0.1620 0.0530 ;
      LAYER M1 ;
        RECT 0.1425 0.0960 0.1575 0.0240 ;
        RECT 0.1125 0.1200 0.1275 0.0480 ;
      LAYER M0 ;
        RECT 0.1350 0.0430 0.1695 0.0290 ;
        RECT 0.1005 0.1150 0.1350 0.1010 ;
    END
  END Y
  PIN A1
    DIRECTION INPUT ;
    USE SIGNAL ;
    PORT
      LAYER M2 ;
        RECT 0.0450 0.1150 0.2250 0.1010 ;
      LAYER M1 ;
        RECT 0.0525 0.1200 0.0675 0.0480 ;
        RECT 0.2025 0.1200 0.2175 0.0240 ;
      LAYER M0 ;
        RECT 0.0330 0.1150 0.0720 0.1010 ;
        RECT 0.1980 0.0430 0.2370 0.0290 ;
    END
  END A1
  PIN A3
    DIRECTION INPUT ;
    USE SIGNAL ;
    PORT
      LAYER M0 ;
        RECT 0.0675 0.0430 0.1020 0.0290 ;
    END
  END A3
  PIN A2
    DIRECTION INPUT ;
    USE SIGNAL ;
    PORT
      LAYER M0 ;
        RECT 0.1680 0.1150 0.2025 0.1010 ;
    END
  END A2
  PIN VDD
    DIRECTION INOUT ;
    USE POWER ;
    SHAPE ABUTMENT ;
    PORT
      LAYER M0 ;
        RECT 0.0000 0.1260 0.2700 0.1620 ;
    END
  END VDD
  PIN VSS
    DIRECTION INOUT ;
    USE GROUND ;
    SHAPE ABUTMENT ;
    PORT
      LAYER M0 ;
        RECT 0.0000 -0.0180 0.2700 0.0180 ;
    END
  END VSS
  OBS
      LAYER V0 ;
        RECT 0.0230 0.0770 0.0370 0.0910 ;
        RECT 0.0230 0.0530 0.0370 0.0670 ;
        RECT 0.1130 0.1010 0.1270 0.1150 ;
        RECT 0.1430 0.0290 0.1570 0.0430 ;
        RECT 0.0530 0.1010 0.0670 0.1150 ;
        RECT 0.2030 0.0290 0.2170 0.0430 ;
      LAYER M1 ;
        RECT 0.0225 0.0960 0.0375 0.0240 ;
      LAYER M0 ;
        RECT 0.0105 0.0530 0.0450 0.0670 ;
        RECT 0.1005 0.0530 0.2145 0.0670 ;
        RECT 0.0180 0.0770 0.2595 0.0910 ;
      LAYER V1 ;
        RECT 0.1130 0.0530 0.1270 0.0670 ;
        RECT 0.1430 0.0530 0.1570 0.0670 ;
        RECT 0.0530 0.1010 0.0670 0.1150 ;
        RECT 0.2030 0.1010 0.2170 0.1150 ;
  END
END 3input0x37_X1

MACRO 3input0x36_X1
  CLASS CORE ;
  ORIGIN 0 0 ;
  FOREIGN 3input0x36_X1 0 0 ;
  SIZE 0.2250 BY 0.1440 ;
  SYMMETRY X Y ;
  SITE coresite ;
  PIN Y
    DIRECTION OUTPUT ;
    USE SIGNAL ;
    PORT
      LAYER M1 ;
        RECT 0.0225 0.1200 0.0375 0.0480 ;
      LAYER M0 ;
        RECT 0.0105 0.0670 0.0450 0.0530 ;
        RECT 0.0180 0.1150 0.0795 0.1010 ;
    END
  END Y
  PIN A3
    DIRECTION INPUT ;
    USE SIGNAL ;
    PORT
      LAYER M0 ;
        RECT 0.0225 0.0430 0.0570 0.0290 ;
    END
  END A3
  PIN A1
    DIRECTION INPUT ;
    USE SIGNAL ;
    PORT
      LAYER M0 ;
        RECT 0.1680 0.0430 0.2025 0.0290 ;
    END
  END A1
  PIN A2
    DIRECTION INPUT ;
    USE SIGNAL ;
    PORT
      LAYER M0 ;
        RECT 0.1125 0.1150 0.1470 0.1010 ;
    END
  END A2
  PIN VDD
    DIRECTION INOUT ;
    USE POWER ;
    SHAPE ABUTMENT ;
    PORT
      LAYER M0 ;
        RECT 0.0000 0.1260 0.2250 0.1620 ;
    END
  END VDD
  PIN VSS
    DIRECTION INOUT ;
    USE GROUND ;
    SHAPE ABUTMENT ;
    PORT
      LAYER M0 ;
        RECT 0.0000 -0.0180 0.2250 0.0180 ;
    END
  END VSS
  OBS
      LAYER M0 ;
        RECT 0.0780 0.0530 0.2145 0.0670 ;
        RECT 0.0780 0.0770 0.1695 0.0910 ;
      LAYER V0 ;
        RECT 0.0230 0.1010 0.0370 0.1150 ;
        RECT 0.0230 0.0530 0.0370 0.0670 ;
  END
END 3input0x36_X1

MACRO 3input0x35_X1
  CLASS CORE ;
  ORIGIN 0 0 ;
  FOREIGN 3input0x35_X1 0 0 ;
  SIZE 0.4050 BY 0.1440 ;
  SYMMETRY X Y ;
  SITE coresite ;
  PIN A1
    DIRECTION INPUT ;
    USE SIGNAL ;
    PORT
      LAYER M2 ;
        RECT 0.0450 0.0670 0.3150 0.0530 ;
      LAYER M1 ;
        RECT 0.0525 0.0960 0.0675 0.0240 ;
        RECT 0.2925 0.0960 0.3075 0.0240 ;
      LAYER M0 ;
        RECT 0.0330 0.0430 0.0720 0.0290 ;
        RECT 0.2880 0.0430 0.3270 0.0290 ;
    END
  END A1
  PIN A2
    DIRECTION INPUT ;
    USE SIGNAL ;
    PORT
      LAYER M2 ;
        RECT 0.0780 0.0910 0.3420 0.0770 ;
      LAYER M1 ;
        RECT 0.0825 0.1200 0.0975 0.0480 ;
        RECT 0.3225 0.1200 0.3375 0.0480 ;
      LAYER M0 ;
        RECT 0.0675 0.1150 0.1020 0.1010 ;
        RECT 0.3150 0.1150 0.3720 0.1010 ;
    END
  END A2
  PIN Y
    DIRECTION OUTPUT ;
    USE SIGNAL ;
    PORT
      LAYER M0 ;
        RECT 0.0105 0.0670 0.1695 0.0530 ;
    END
  END Y
  PIN Y
    DIRECTION OUTPUT ;
    USE SIGNAL ;
    PORT
      LAYER M0 ;
        RECT 0.1455 0.0910 0.2145 0.0770 ;
    END
  END Y
  PIN A3
    DIRECTION INPUT ;
    USE SIGNAL ;
    PORT
      LAYER M0 ;
        RECT 0.1230 0.1150 0.2820 0.1010 ;
    END
  END A3
  PIN VDD
    DIRECTION INOUT ;
    USE POWER ;
    SHAPE ABUTMENT ;
    PORT
      LAYER M0 ;
        RECT 0.0000 0.1260 0.4050 0.1620 ;
    END
  END VDD
  PIN VSS
    DIRECTION INOUT ;
    USE GROUND ;
    SHAPE ABUTMENT ;
    PORT
      LAYER M0 ;
        RECT 0.0000 -0.0180 0.4050 0.0180 ;
    END
  END VSS
  OBS
      LAYER M0 ;
        RECT 0.1005 0.0290 0.2145 0.0430 ;
        RECT 0.2130 0.0530 0.3945 0.0670 ;
        RECT 0.0105 0.0770 0.1245 0.0910 ;
        RECT 0.2805 0.0770 0.3945 0.0910 ;
      LAYER V0 ;
        RECT 0.0830 0.1010 0.0970 0.1150 ;
        RECT 0.3230 0.1010 0.3370 0.1150 ;
        RECT 0.0530 0.0290 0.0670 0.0430 ;
        RECT 0.2930 0.0290 0.3070 0.0430 ;
      LAYER V1 ;
        RECT 0.0830 0.0770 0.0970 0.0910 ;
        RECT 0.3230 0.0770 0.3370 0.0910 ;
        RECT 0.0530 0.0530 0.0670 0.0670 ;
        RECT 0.2930 0.0530 0.3070 0.0670 ;
  END
END 3input0x35_X1

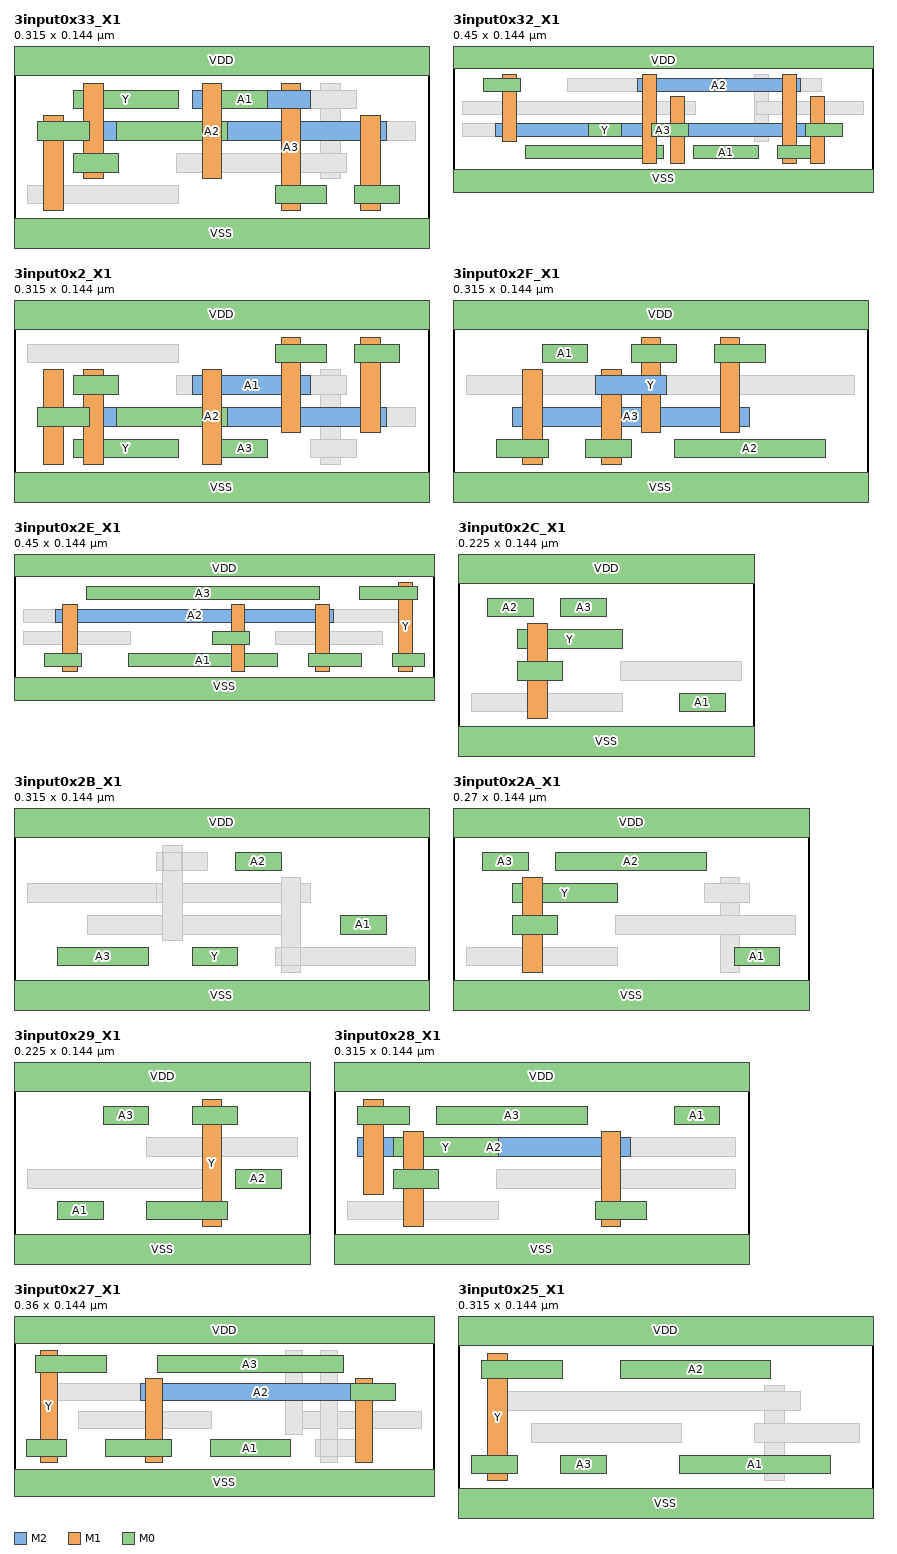
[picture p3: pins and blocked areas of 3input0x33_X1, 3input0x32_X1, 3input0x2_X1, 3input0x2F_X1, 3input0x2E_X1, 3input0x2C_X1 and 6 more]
MACRO 3input0x33_X1
  CLASS CORE ;
  ORIGIN 0 0 ;
  FOREIGN 3input0x33_X1 0 0 ;
  SIZE 0.3150 BY 0.1440 ;
  SYMMETRY X Y ;
  SITE coresite ;
  PIN Y
    DIRECTION OUTPUT ;
    USE SIGNAL ;
    PORT
      LAYER M1 ;
        RECT 0.0525 0.1200 0.0675 0.0480 ;
      LAYER M0 ;
        RECT 0.0450 0.0670 0.0795 0.0530 ;
        RECT 0.0450 0.1150 0.1245 0.1010 ;
    END
  END Y
  PIN A2
    DIRECTION INPUT ;
    USE SIGNAL ;
    PORT
      LAYER M2 ;
        RECT 0.0180 0.0910 0.2820 0.0770 ;
      LAYER M1 ;
        RECT 0.0225 0.0960 0.0375 0.0240 ;
        RECT 0.2625 0.0960 0.2775 0.0240 ;
      LAYER M0 ;
        RECT 0.0180 0.0910 0.0570 0.0770 ;
        RECT 0.2580 0.0430 0.2925 0.0290 ;
    END
  END A2
  PIN A3
    DIRECTION INPUT ;
    USE SIGNAL ;
    PORT
      LAYER M2 ;
        RECT 0.1350 0.1150 0.2250 0.1010 ;
      LAYER M1 ;
        RECT 0.1425 0.1200 0.1575 0.0480 ;
        RECT 0.2025 0.1200 0.2175 0.0240 ;
      LAYER M0 ;
        RECT 0.0780 0.0910 0.1620 0.0770 ;
        RECT 0.1980 0.0430 0.2370 0.0290 ;
    END
  END A3
  PIN A1
    DIRECTION INPUT ;
    USE SIGNAL ;
    PORT
      LAYER M0 ;
        RECT 0.1575 0.1150 0.1920 0.1010 ;
    END
  END A1
  PIN VDD
    DIRECTION INOUT ;
    USE POWER ;
    SHAPE ABUTMENT ;
    PORT
      LAYER M0 ;
        RECT 0.0000 0.1260 0.3150 0.1620 ;
    END
  END VDD
  PIN VSS
    DIRECTION INOUT ;
    USE GROUND ;
    SHAPE ABUTMENT ;
    PORT
      LAYER M0 ;
        RECT 0.0000 -0.0180 0.3150 0.0180 ;
    END
  END VSS
  OBS
      LAYER V0 ;
        RECT 0.1430 0.0770 0.1570 0.0910 ;
        RECT 0.2030 0.0290 0.2170 0.0430 ;
        RECT 0.0530 0.1010 0.0670 0.1150 ;
        RECT 0.0530 0.0530 0.0670 0.0670 ;
        RECT 0.0230 0.0770 0.0370 0.0910 ;
        RECT 0.2630 0.0290 0.2770 0.0430 ;
        RECT 0.2330 0.1010 0.2470 0.1150 ;
        RECT 0.2330 0.0530 0.2470 0.0670 ;
      LAYER M1 ;
        RECT 0.2325 0.1200 0.2475 0.0480 ;
      LAYER M0 ;
        RECT 0.0105 0.0290 0.1245 0.0430 ;
        RECT 0.1230 0.0530 0.2520 0.0670 ;
        RECT 0.1905 0.0770 0.3045 0.0910 ;
        RECT 0.2250 0.1010 0.2595 0.1150 ;
      LAYER V1 ;
        RECT 0.1430 0.1010 0.1570 0.1150 ;
        RECT 0.2030 0.1010 0.2170 0.1150 ;
        RECT 0.0230 0.0770 0.0370 0.0910 ;
        RECT 0.2630 0.0770 0.2770 0.0910 ;
  END
END 3input0x33_X1

MACRO 3input0x32_X1
  CLASS CORE ;
  ORIGIN 0 0 ;
  FOREIGN 3input0x32_X1 0 0 ;
  SIZE 0.4500 BY 0.1440 ;
  SYMMETRY X Y ;
  SITE coresite ;
  PIN A3
    DIRECTION INPUT ;
    USE SIGNAL ;
    PORT
      LAYER M2 ;
        RECT 0.0450 0.0670 0.4050 0.0530 ;
      LAYER M1 ;
        RECT 0.2325 0.0960 0.2475 0.0240 ;
        RECT 0.3825 0.0960 0.3975 0.0240 ;
        RECT 0.0525 0.1200 0.0675 0.0480 ;
      LAYER M0 ;
        RECT 0.2130 0.0670 0.2520 0.0530 ;
        RECT 0.3780 0.0670 0.4170 0.0530 ;
        RECT 0.0330 0.1150 0.0720 0.1010 ;
    END
  END A3
  PIN A2
    DIRECTION INPUT ;
    USE SIGNAL ;
    PORT
      LAYER M2 ;
        RECT 0.1980 0.1150 0.3720 0.1010 ;
      LAYER M1 ;
        RECT 0.2025 0.1200 0.2175 0.0240 ;
        RECT 0.3525 0.1200 0.3675 0.0240 ;
      LAYER M0 ;
        RECT 0.0780 0.0430 0.2250 0.0290 ;
        RECT 0.3480 0.0430 0.3825 0.0290 ;
    END
  END A2
  PIN A1
    DIRECTION INPUT ;
    USE SIGNAL ;
    PORT
      LAYER M0 ;
        RECT 0.2580 0.0430 0.3270 0.0290 ;
    END
  END A1
  PIN Y
    DIRECTION OUTPUT ;
    USE SIGNAL ;
    PORT
      LAYER M0 ;
        RECT 0.1455 0.0670 0.1800 0.0530 ;
    END
  END Y
  PIN VDD
    DIRECTION INOUT ;
    USE POWER ;
    SHAPE ABUTMENT ;
    PORT
      LAYER M0 ;
        RECT 0.0000 0.1260 0.4500 0.1620 ;
    END
  END VDD
  PIN VSS
    DIRECTION INOUT ;
    USE GROUND ;
    SHAPE ABUTMENT ;
    PORT
      LAYER M0 ;
        RECT 0.0000 -0.0180 0.4500 0.0180 ;
    END
  END VSS
  OBS
      LAYER V0 ;
        RECT 0.3230 0.1010 0.3370 0.1150 ;
        RECT 0.3230 0.0530 0.3370 0.0670 ;
        RECT 0.0530 0.1010 0.0670 0.1150 ;
        RECT 0.2330 0.0530 0.2470 0.0670 ;
        RECT 0.3830 0.0530 0.3970 0.0670 ;
        RECT 0.2030 0.0290 0.2170 0.0430 ;
        RECT 0.3530 0.0290 0.3670 0.0430 ;
      LAYER M1 ;
        RECT 0.3225 0.1200 0.3375 0.0480 ;
      LAYER M0 ;
        RECT 0.0105 0.0530 0.1245 0.0670 ;
        RECT 0.3150 0.0530 0.3495 0.0670 ;
        RECT 0.0105 0.0770 0.2595 0.0910 ;
        RECT 0.3255 0.0770 0.4395 0.0910 ;
        RECT 0.1230 0.1010 0.3945 0.1150 ;
      LAYER V1 ;
        RECT 0.0530 0.0530 0.0670 0.0670 ;
        RECT 0.2330 0.0530 0.2470 0.0670 ;
        RECT 0.3830 0.0530 0.3970 0.0670 ;
        RECT 0.2030 0.1010 0.2170 0.1150 ;
        RECT 0.3530 0.1010 0.3670 0.1150 ;
  END
END 3input0x32_X1

MACRO 3input0x2_X1
  CLASS CORE ;
  ORIGIN 0 0 ;
  FOREIGN 3input0x2_X1 0 0 ;
  SIZE 0.3150 BY 0.1440 ;
  SYMMETRY X Y ;
  SITE coresite ;
  PIN Y
    DIRECTION OUTPUT ;
    USE SIGNAL ;
    PORT
      LAYER M1 ;
        RECT 0.0525 0.0960 0.0675 0.0240 ;
      LAYER M0 ;
        RECT 0.0450 0.0430 0.1245 0.0290 ;
        RECT 0.0450 0.0910 0.0795 0.0770 ;
    END
  END Y
  PIN A2
    DIRECTION INPUT ;
    USE SIGNAL ;
    PORT
      LAYER M2 ;
        RECT 0.0180 0.0670 0.2820 0.0530 ;
      LAYER M1 ;
        RECT 0.0225 0.0960 0.0375 0.0240 ;
        RECT 0.2625 0.1200 0.2775 0.0480 ;
      LAYER M0 ;
        RECT 0.0180 0.0670 0.0570 0.0530 ;
        RECT 0.2580 0.1150 0.2925 0.1010 ;
    END
  END A2
  PIN A1
    DIRECTION INPUT ;
    USE SIGNAL ;
    PORT
      LAYER M2 ;
        RECT 0.1350 0.0910 0.2250 0.0770 ;
      LAYER M1 ;
        RECT 0.1425 0.0960 0.1575 0.0240 ;
        RECT 0.2025 0.1200 0.2175 0.0480 ;
      LAYER M0 ;
        RECT 0.0780 0.0670 0.1620 0.0530 ;
        RECT 0.1980 0.1150 0.2370 0.1010 ;
    END
  END A1
  PIN A3
    DIRECTION INPUT ;
    USE SIGNAL ;
    PORT
      LAYER M0 ;
        RECT 0.1575 0.0430 0.1920 0.0290 ;
    END
  END A3
  PIN VDD
    DIRECTION INOUT ;
    USE POWER ;
    SHAPE ABUTMENT ;
    PORT
      LAYER M0 ;
        RECT 0.0000 0.1260 0.3150 0.1620 ;
    END
  END VDD
  PIN VSS
    DIRECTION INOUT ;
    USE GROUND ;
    SHAPE ABUTMENT ;
    PORT
      LAYER M0 ;
        RECT 0.0000 -0.0180 0.3150 0.0180 ;
    END
  END VSS
  OBS
      LAYER V0 ;
        RECT 0.2330 0.0770 0.2470 0.0910 ;
        RECT 0.2330 0.0290 0.2470 0.0430 ;
        RECT 0.0230 0.0530 0.0370 0.0670 ;
        RECT 0.2630 0.1010 0.2770 0.1150 ;
        RECT 0.1430 0.0530 0.1570 0.0670 ;
        RECT 0.2030 0.1010 0.2170 0.1150 ;
        RECT 0.0530 0.0770 0.0670 0.0910 ;
        RECT 0.0530 0.0290 0.0670 0.0430 ;
      LAYER M1 ;
        RECT 0.2325 0.0960 0.2475 0.0240 ;
      LAYER M0 ;
        RECT 0.2250 0.0290 0.2595 0.0430 ;
        RECT 0.1905 0.0530 0.3045 0.0670 ;
        RECT 0.1230 0.0770 0.2520 0.0910 ;
        RECT 0.0105 0.1010 0.1245 0.1150 ;
      LAYER V1 ;
        RECT 0.0230 0.0530 0.0370 0.0670 ;
        RECT 0.2630 0.0530 0.2770 0.0670 ;
        RECT 0.1430 0.0770 0.1570 0.0910 ;
        RECT 0.2030 0.0770 0.2170 0.0910 ;
  END
END 3input0x2_X1

MACRO 3input0x2F_X1
  CLASS CORE ;
  ORIGIN 0 0 ;
  FOREIGN 3input0x2F_X1 0 0 ;
  SIZE 0.3150 BY 0.1440 ;
  SYMMETRY X Y ;
  SITE coresite ;
  PIN A3
    DIRECTION INPUT ;
    USE SIGNAL ;
    PORT
      LAYER M2 ;
        RECT 0.0450 0.0670 0.2250 0.0530 ;
      LAYER M1 ;
        RECT 0.0525 0.0960 0.0675 0.0240 ;
        RECT 0.2025 0.1200 0.2175 0.0480 ;
      LAYER M0 ;
        RECT 0.0330 0.0430 0.0720 0.0290 ;
        RECT 0.1980 0.1150 0.2370 0.1010 ;
    END
  END A3
  PIN Y
    DIRECTION OUTPUT ;
    USE SIGNAL ;
    PORT
      LAYER M2 ;
        RECT 0.1080 0.0910 0.1620 0.0770 ;
      LAYER M1 ;
        RECT 0.1125 0.0960 0.1275 0.0240 ;
        RECT 0.1425 0.1200 0.1575 0.0480 ;
      LAYER M0 ;
        RECT 0.1005 0.0430 0.1350 0.0290 ;
        RECT 0.1350 0.1150 0.1695 0.1010 ;
    END
  END Y
  PIN A2
    DIRECTION INPUT ;
    USE SIGNAL ;
    PORT
      LAYER M0 ;
        RECT 0.1680 0.0430 0.2820 0.0290 ;
    END
  END A2
  PIN A1
    DIRECTION INPUT ;
    USE SIGNAL ;
    PORT
      LAYER M0 ;
        RECT 0.0675 0.1150 0.1020 0.1010 ;
    END
  END A1
  PIN VDD
    DIRECTION INOUT ;
    USE POWER ;
    SHAPE ABUTMENT ;
    PORT
      LAYER M0 ;
        RECT 0.0000 0.1260 0.3150 0.1620 ;
    END
  END VDD
  PIN VSS
    DIRECTION INOUT ;
    USE GROUND ;
    SHAPE ABUTMENT ;
    PORT
      LAYER M0 ;
        RECT 0.0000 -0.0180 0.3150 0.0180 ;
    END
  END VSS
  OBS
      LAYER M0 ;
        RECT 0.0555 0.0530 0.1695 0.0670 ;
        RECT 0.0105 0.0770 0.3045 0.0910 ;
      LAYER V0 ;
        RECT 0.0530 0.0290 0.0670 0.0430 ;
        RECT 0.2030 0.1010 0.2170 0.1150 ;
        RECT 0.1130 0.0290 0.1270 0.0430 ;
        RECT 0.1430 0.1010 0.1570 0.1150 ;
      LAYER V1 ;
        RECT 0.0530 0.0530 0.0670 0.0670 ;
        RECT 0.2030 0.0530 0.2170 0.0670 ;
        RECT 0.1130 0.0770 0.1270 0.0910 ;
        RECT 0.1430 0.0770 0.1570 0.0910 ;
  END
END 3input0x2F_X1

MACRO 3input0x2E_X1
  CLASS CORE ;
  ORIGIN 0 0 ;
  FOREIGN 3input0x2E_X1 0 0 ;
  SIZE 0.4500 BY 0.1440 ;
  SYMMETRY X Y ;
  SITE coresite ;
  PIN Y
    DIRECTION OUTPUT ;
    USE SIGNAL ;
    PORT
      LAYER M1 ;
        RECT 0.4125 0.1200 0.4275 0.0240 ;
      LAYER M0 ;
        RECT 0.4050 0.0430 0.4395 0.0290 ;
        RECT 0.3705 0.1150 0.4320 0.1010 ;
    END
  END Y
  PIN A2
    DIRECTION INPUT ;
    USE SIGNAL ;
    PORT
      LAYER M2 ;
        RECT 0.0450 0.0910 0.3420 0.0770 ;
      LAYER M1 ;
        RECT 0.0525 0.0960 0.0675 0.0240 ;
        RECT 0.2325 0.0960 0.2475 0.0240 ;
        RECT 0.3225 0.0960 0.3375 0.0240 ;
      LAYER M0 ;
        RECT 0.0330 0.0430 0.0720 0.0290 ;
        RECT 0.2130 0.0670 0.2520 0.0530 ;
        RECT 0.3150 0.0430 0.3720 0.0290 ;
    END
  END A2
  PIN A1
    DIRECTION INPUT ;
    USE SIGNAL ;
    PORT
      LAYER M0 ;
        RECT 0.1230 0.0430 0.2820 0.0290 ;
    END
  END A1
  PIN A3
    DIRECTION INPUT ;
    USE SIGNAL ;
    PORT
      LAYER M0 ;
        RECT 0.0780 0.1150 0.3270 0.1010 ;
    END
  END A3
  PIN VDD
    DIRECTION INOUT ;
    USE POWER ;
    SHAPE ABUTMENT ;
    PORT
      LAYER M0 ;
        RECT 0.0000 0.1260 0.4500 0.1620 ;
    END
  END VDD
  PIN VSS
    DIRECTION INOUT ;
    USE GROUND ;
    SHAPE ABUTMENT ;
    PORT
      LAYER M0 ;
        RECT 0.0000 -0.0180 0.4500 0.0180 ;
    END
  END VSS
  OBS
      LAYER M0 ;
        RECT 0.0105 0.0530 0.1245 0.0670 ;
        RECT 0.2805 0.0530 0.3945 0.0670 ;
        RECT 0.0105 0.0770 0.1245 0.0910 ;
        RECT 0.1455 0.0770 0.4170 0.0910 ;
      LAYER V0 ;
        RECT 0.0530 0.0290 0.0670 0.0430 ;
        RECT 0.2330 0.0530 0.2470 0.0670 ;
        RECT 0.3230 0.0290 0.3370 0.0430 ;
        RECT 0.4130 0.1010 0.4270 0.1150 ;
        RECT 0.4130 0.0290 0.4270 0.0430 ;
      LAYER V1 ;
        RECT 0.0530 0.0770 0.0670 0.0910 ;
        RECT 0.2330 0.0770 0.2470 0.0910 ;
        RECT 0.3230 0.0770 0.3370 0.0910 ;
  END
END 3input0x2E_X1

MACRO 3input0x2C_X1
  CLASS CORE ;
  ORIGIN 0 0 ;
  FOREIGN 3input0x2C_X1 0 0 ;
  SIZE 0.2250 BY 0.1440 ;
  SYMMETRY X Y ;
  SITE coresite ;
  PIN Y
    DIRECTION OUTPUT ;
    USE SIGNAL ;
    PORT
      LAYER M1 ;
        RECT 0.0525 0.0960 0.0675 0.0240 ;
      LAYER M0 ;
        RECT 0.0450 0.0670 0.0795 0.0530 ;
        RECT 0.0450 0.0910 0.1245 0.0770 ;
    END
  END Y
  PIN A1
    DIRECTION INPUT ;
    USE SIGNAL ;
    PORT
      LAYER M0 ;
        RECT 0.1680 0.0430 0.2025 0.0290 ;
    END
  END A1
  PIN A2
    DIRECTION INPUT ;
    USE SIGNAL ;
    PORT
      LAYER M0 ;
        RECT 0.0225 0.1150 0.0570 0.1010 ;
    END
  END A2
  PIN A3
    DIRECTION INPUT ;
    USE SIGNAL ;
    PORT
      LAYER M0 ;
        RECT 0.0780 0.1150 0.1125 0.1010 ;
    END
  END A3
  PIN VDD
    DIRECTION INOUT ;
    USE POWER ;
    SHAPE ABUTMENT ;
    PORT
      LAYER M0 ;
        RECT 0.0000 0.1260 0.2250 0.1620 ;
    END
  END VDD
  PIN VSS
    DIRECTION INOUT ;
    USE GROUND ;
    SHAPE ABUTMENT ;
    PORT
      LAYER M0 ;
        RECT 0.0000 -0.0180 0.2250 0.0180 ;
    END
  END VSS
  OBS
      LAYER M0 ;
        RECT 0.0105 0.0290 0.1245 0.0430 ;
        RECT 0.1230 0.0530 0.2145 0.0670 ;
      LAYER V0 ;
        RECT 0.0530 0.0770 0.0670 0.0910 ;
        RECT 0.0530 0.0530 0.0670 0.0670 ;
  END
END 3input0x2C_X1

MACRO 3input0x2B_X1
  CLASS CORE ;
  ORIGIN 0 0 ;
  FOREIGN 3input0x2B_X1 0 0 ;
  SIZE 0.3150 BY 0.1440 ;
  SYMMETRY X Y ;
  SITE coresite ;
  PIN A3
    DIRECTION INPUT ;
    USE SIGNAL ;
    PORT
      LAYER M0 ;
        RECT 0.0330 0.0430 0.1020 0.0290 ;
    END
  END A3
  PIN Y
    DIRECTION OUTPUT ;
    USE SIGNAL ;
    PORT
      LAYER M0 ;
        RECT 0.1350 0.0430 0.1695 0.0290 ;
    END
  END Y
  PIN A1
    DIRECTION INPUT ;
    USE SIGNAL ;
    PORT
      LAYER M0 ;
        RECT 0.2475 0.0670 0.2820 0.0530 ;
    END
  END A1
  PIN A2
    DIRECTION INPUT ;
    USE SIGNAL ;
    PORT
      LAYER M0 ;
        RECT 0.1680 0.1150 0.2025 0.1010 ;
    END
  END A2
  PIN VDD
    DIRECTION INOUT ;
    USE POWER ;
    SHAPE ABUTMENT ;
    PORT
      LAYER M0 ;
        RECT 0.0000 0.1260 0.3150 0.1620 ;
    END
  END VDD
  PIN VSS
    DIRECTION INOUT ;
    USE GROUND ;
    SHAPE ABUTMENT ;
    PORT
      LAYER M0 ;
        RECT 0.0000 -0.0180 0.3150 0.0180 ;
    END
  END VSS
  OBS
      LAYER V1 ;
        RECT 0.1130 0.0770 0.1270 0.0910 ;
        RECT 0.2030 0.0770 0.2170 0.0910 ;
      LAYER M0 ;
        RECT 0.1980 0.0290 0.3045 0.0430 ;
        RECT 0.0555 0.0530 0.2145 0.0670 ;
        RECT 0.0105 0.0770 0.2145 0.0910 ;
        RECT 0.1080 0.1010 0.1470 0.1150 ;
      LAYER M2 ;
        RECT 0.1080 0.0770 0.2250 0.0910 ;
      LAYER M1 ;
        RECT 0.2025 0.0960 0.2175 0.0240 ;
        RECT 0.1125 0.1200 0.1275 0.0480 ;
      LAYER V0 ;
        RECT 0.1130 0.1010 0.1270 0.1150 ;
        RECT 0.2030 0.0290 0.2170 0.0430 ;
  END
END 3input0x2B_X1

MACRO 3input0x2A_X1
  CLASS CORE ;
  ORIGIN 0 0 ;
  FOREIGN 3input0x2A_X1 0 0 ;
  SIZE 0.2700 BY 0.1440 ;
  SYMMETRY X Y ;
  SITE coresite ;
  PIN Y
    DIRECTION OUTPUT ;
    USE SIGNAL ;
    PORT
      LAYER M1 ;
        RECT 0.0525 0.0960 0.0675 0.0240 ;
      LAYER M0 ;
        RECT 0.0450 0.0670 0.0795 0.0530 ;
        RECT 0.0450 0.0910 0.1245 0.0770 ;
    END
  END Y
  PIN A1
    DIRECTION INPUT ;
    USE SIGNAL ;
    PORT
      LAYER M0 ;
        RECT 0.2130 0.0430 0.2475 0.0290 ;
    END
  END A1
  PIN A3
    DIRECTION INPUT ;
    USE SIGNAL ;
    PORT
      LAYER M0 ;
        RECT 0.0225 0.1150 0.0570 0.1010 ;
    END
  END A3
  PIN A2
    DIRECTION INPUT ;
    USE SIGNAL ;
    PORT
      LAYER M0 ;
        RECT 0.0780 0.1150 0.1920 0.1010 ;
    END
  END A2
  PIN VDD
    DIRECTION INOUT ;
    USE POWER ;
    SHAPE ABUTMENT ;
    PORT
      LAYER M0 ;
        RECT 0.0000 0.1260 0.2700 0.1620 ;
    END
  END VDD
  PIN VSS
    DIRECTION INOUT ;
    USE GROUND ;
    SHAPE ABUTMENT ;
    PORT
      LAYER M0 ;
        RECT 0.0000 -0.0180 0.2700 0.0180 ;
    END
  END VSS
  OBS
      LAYER V0 ;
        RECT 0.0530 0.0770 0.0670 0.0910 ;
        RECT 0.0530 0.0530 0.0670 0.0670 ;
        RECT 0.2030 0.0770 0.2170 0.0910 ;
        RECT 0.2030 0.0530 0.2170 0.0670 ;
      LAYER M1 ;
        RECT 0.2025 0.0960 0.2175 0.0240 ;
      LAYER M0 ;
        RECT 0.0105 0.0290 0.1245 0.0430 ;
        RECT 0.1230 0.0530 0.2595 0.0670 ;
        RECT 0.1905 0.0770 0.2250 0.0910 ;
  END
END 3input0x2A_X1

MACRO 3input0x29_X1
  CLASS CORE ;
  ORIGIN 0 0 ;
  FOREIGN 3input0x29_X1 0 0 ;
  SIZE 0.2250 BY 0.1440 ;
  SYMMETRY X Y ;
  SITE coresite ;
  PIN Y
    DIRECTION OUTPUT ;
    USE SIGNAL ;
    PORT
      LAYER M1 ;
        RECT 0.1425 0.1200 0.1575 0.0240 ;
      LAYER M0 ;
        RECT 0.1005 0.0430 0.1620 0.0290 ;
        RECT 0.1350 0.1150 0.1695 0.1010 ;
    END
  END Y
  PIN A1
    DIRECTION INPUT ;
    USE SIGNAL ;
    PORT
      LAYER M0 ;
        RECT 0.0330 0.0430 0.0675 0.0290 ;
    END
  END A1
  PIN A2
    DIRECTION INPUT ;
    USE SIGNAL ;
    PORT
      LAYER M0 ;
        RECT 0.1680 0.0670 0.2025 0.0530 ;
    END
  END A2
  PIN A3
    DIRECTION INPUT ;
    USE SIGNAL ;
    PORT
      LAYER M0 ;
        RECT 0.0675 0.1150 0.1020 0.1010 ;
    END
  END A3
  PIN VDD
    DIRECTION INOUT ;
    USE POWER ;
    SHAPE ABUTMENT ;
    PORT
      LAYER M0 ;
        RECT 0.0000 0.1260 0.2250 0.1620 ;
    END
  END VDD
  PIN VSS
    DIRECTION INOUT ;
    USE GROUND ;
    SHAPE ABUTMENT ;
    PORT
      LAYER M0 ;
        RECT 0.0000 -0.0180 0.2250 0.0180 ;
    END
  END VSS
  OBS
      LAYER M0 ;
        RECT 0.0105 0.0530 0.1470 0.0670 ;
        RECT 0.1005 0.0770 0.2145 0.0910 ;
      LAYER V0 ;
        RECT 0.1430 0.1010 0.1570 0.1150 ;
        RECT 0.1430 0.0290 0.1570 0.0430 ;
  END
END 3input0x29_X1

MACRO 3input0x28_X1
  CLASS CORE ;
  ORIGIN 0 0 ;
  FOREIGN 3input0x28_X1 0 0 ;
  SIZE 0.3150 BY 0.1440 ;
  SYMMETRY X Y ;
  SITE coresite ;
  PIN Y
    DIRECTION OUTPUT ;
    USE SIGNAL ;
    PORT
      LAYER M1 ;
        RECT 0.0525 0.0960 0.0675 0.0240 ;
      LAYER M0 ;
        RECT 0.0450 0.0670 0.0795 0.0530 ;
        RECT 0.0450 0.0910 0.1245 0.0770 ;
    END
  END Y
  PIN A2
    DIRECTION INPUT ;
    USE SIGNAL ;
    PORT
      LAYER M2 ;
        RECT 0.0180 0.0910 0.2250 0.0770 ;
      LAYER M1 ;
        RECT 0.2025 0.0960 0.2175 0.0240 ;
        RECT 0.0225 0.1200 0.0375 0.0480 ;
      LAYER M0 ;
        RECT 0.1980 0.0430 0.2370 0.0290 ;
        RECT 0.0180 0.1150 0.0570 0.1010 ;
    END
  END A2
  PIN A3
    DIRECTION INPUT ;
    USE SIGNAL ;
    PORT
      LAYER M0 ;
        RECT 0.0780 0.1150 0.1920 0.1010 ;
    END
  END A3
  PIN A1
    DIRECTION INPUT ;
    USE SIGNAL ;
    PORT
      LAYER M0 ;
        RECT 0.2580 0.1150 0.2925 0.1010 ;
    END
  END A1
  PIN VDD
    DIRECTION INOUT ;
    USE POWER ;
    SHAPE ABUTMENT ;
    PORT
      LAYER M0 ;
        RECT 0.0000 0.1260 0.3150 0.1620 ;
    END
  END VDD
  PIN VSS
    DIRECTION INOUT ;
    USE GROUND ;
    SHAPE ABUTMENT ;
    PORT
      LAYER M0 ;
        RECT 0.0000 -0.0180 0.3150 0.0180 ;
    END
  END VSS
  OBS
      LAYER M0 ;
        RECT 0.0105 0.0290 0.1245 0.0430 ;
        RECT 0.1230 0.0530 0.3045 0.0670 ;
        RECT 0.1905 0.0770 0.3045 0.0910 ;
      LAYER V0 ;
        RECT 0.0530 0.0770 0.0670 0.0910 ;
        RECT 0.0530 0.0530 0.0670 0.0670 ;
        RECT 0.0230 0.1010 0.0370 0.1150 ;
        RECT 0.2030 0.0290 0.2170 0.0430 ;
      LAYER V1 ;
        RECT 0.0230 0.0770 0.0370 0.0910 ;
        RECT 0.2030 0.0770 0.2170 0.0910 ;
  END
END 3input0x28_X1

MACRO 3input0x27_X1
  CLASS CORE ;
  ORIGIN 0 0 ;
  FOREIGN 3input0x27_X1 0 0 ;
  SIZE 0.3600 BY 0.1440 ;
  SYMMETRY X Y ;
  SITE coresite ;
  PIN Y
    DIRECTION OUTPUT ;
    USE SIGNAL ;
    PORT
      LAYER M1 ;
        RECT 0.0225 0.1200 0.0375 0.0240 ;
      LAYER M0 ;
        RECT 0.0105 0.0430 0.0450 0.0290 ;
        RECT 0.0180 0.1150 0.0795 0.1010 ;
    END
  END Y
  PIN A2
    DIRECTION INPUT ;
    USE SIGNAL ;
    PORT
      LAYER M2 ;
        RECT 0.1080 0.0910 0.3150 0.0770 ;
      LAYER M1 ;
        RECT 0.1125 0.0960 0.1275 0.0240 ;
        RECT 0.2925 0.0960 0.3075 0.0240 ;
      LAYER M0 ;
        RECT 0.0780 0.0430 0.1350 0.0290 ;
        RECT 0.2880 0.0910 0.3270 0.0770 ;
    END
  END A2
  PIN A1
    DIRECTION INPUT ;
    USE SIGNAL ;
    PORT
      LAYER M0 ;
        RECT 0.1680 0.0430 0.2370 0.0290 ;
    END
  END A1
  PIN A3
    DIRECTION INPUT ;
    USE SIGNAL ;
    PORT
      LAYER M0 ;
        RECT 0.1230 0.1150 0.2820 0.1010 ;
    END
  END A3
  PIN VDD
    DIRECTION INOUT ;
    USE POWER ;
    SHAPE ABUTMENT ;
    PORT
      LAYER M0 ;
        RECT 0.0000 0.1260 0.3600 0.1620 ;
    END
  END VDD
  PIN VSS
    DIRECTION INOUT ;
    USE GROUND ;
    SHAPE ABUTMENT ;
    PORT
      LAYER M0 ;
        RECT 0.0000 -0.0180 0.3600 0.0180 ;
    END
  END VSS
  OBS
      LAYER V1 ;
        RECT 0.2330 0.1010 0.2470 0.1150 ;
        RECT 0.2630 0.1010 0.2770 0.1150 ;
        RECT 0.1130 0.0770 0.1270 0.0910 ;
        RECT 0.2930 0.0770 0.3070 0.0910 ;
      LAYER M0 ;
        RECT 0.2580 0.0290 0.3045 0.0430 ;
        RECT 0.0555 0.0530 0.1695 0.0670 ;
        RECT 0.2355 0.0530 0.3495 0.0670 ;
        RECT 0.0330 0.0770 0.2595 0.0910 ;
      LAYER M2 ;
        RECT 0.2250 0.1010 0.2820 0.1150 ;
      LAYER M1 ;
        RECT 0.2325 0.1200 0.2475 0.0480 ;
        RECT 0.2625 0.1200 0.2775 0.0240 ;
      LAYER V0 ;
        RECT 0.0230 0.1010 0.0370 0.1150 ;
        RECT 0.0230 0.0290 0.0370 0.0430 ;
        RECT 0.2330 0.0770 0.2470 0.0910 ;
        RECT 0.2630 0.0290 0.2770 0.0430 ;
        RECT 0.1130 0.0290 0.1270 0.0430 ;
        RECT 0.2930 0.0770 0.3070 0.0910 ;
  END
END 3input0x27_X1

MACRO 3input0x25_X1
  CLASS CORE ;
  ORIGIN 0 0 ;
  FOREIGN 3input0x25_X1 0 0 ;
  SIZE 0.3150 BY 0.1440 ;
  SYMMETRY X Y ;
  SITE coresite ;
  PIN Y
    DIRECTION OUTPUT ;
    USE SIGNAL ;
    PORT
      LAYER M1 ;
        RECT 0.0225 0.1200 0.0375 0.0240 ;
      LAYER M0 ;
        RECT 0.0105 0.0430 0.0450 0.0290 ;
        RECT 0.0180 0.1150 0.0795 0.1010 ;
    END
  END Y
  PIN A3
    DIRECTION INPUT ;
    USE SIGNAL ;
    PORT
      LAYER M0 ;
        RECT 0.0780 0.0430 0.1125 0.0290 ;
    END
  END A3
  PIN A1
    DIRECTION INPUT ;
    USE SIGNAL ;
    PORT
      LAYER M0 ;
        RECT 0.1680 0.0430 0.2820 0.0290 ;
    END
  END A1
  PIN A2
    DIRECTION INPUT ;
    USE SIGNAL ;
    PORT
      LAYER M0 ;
        RECT 0.1230 0.1150 0.2370 0.1010 ;
    END
  END A2
  PIN VDD
    DIRECTION INOUT ;
    USE POWER ;
    SHAPE ABUTMENT ;
    PORT
      LAYER M0 ;
        RECT 0.0000 0.1260 0.3150 0.1620 ;
    END
  END VDD
  PIN VSS
    DIRECTION INOUT ;
    USE GROUND ;
    SHAPE ABUTMENT ;
    PORT
      LAYER M0 ;
        RECT 0.0000 -0.0180 0.3150 0.0180 ;
    END
  END VSS
  OBS
      LAYER V0 ;
        RECT 0.2330 0.0770 0.2470 0.0910 ;
        RECT 0.2330 0.0530 0.2470 0.0670 ;
        RECT 0.0230 0.1010 0.0370 0.1150 ;
        RECT 0.0230 0.0290 0.0370 0.0430 ;
      LAYER M1 ;
        RECT 0.2325 0.0960 0.2475 0.0240 ;
      LAYER M0 ;
        RECT 0.0555 0.0530 0.1695 0.0670 ;
        RECT 0.2250 0.0530 0.3045 0.0670 ;
        RECT 0.0330 0.0770 0.2595 0.0910 ;
  END
END 3input0x25_X1

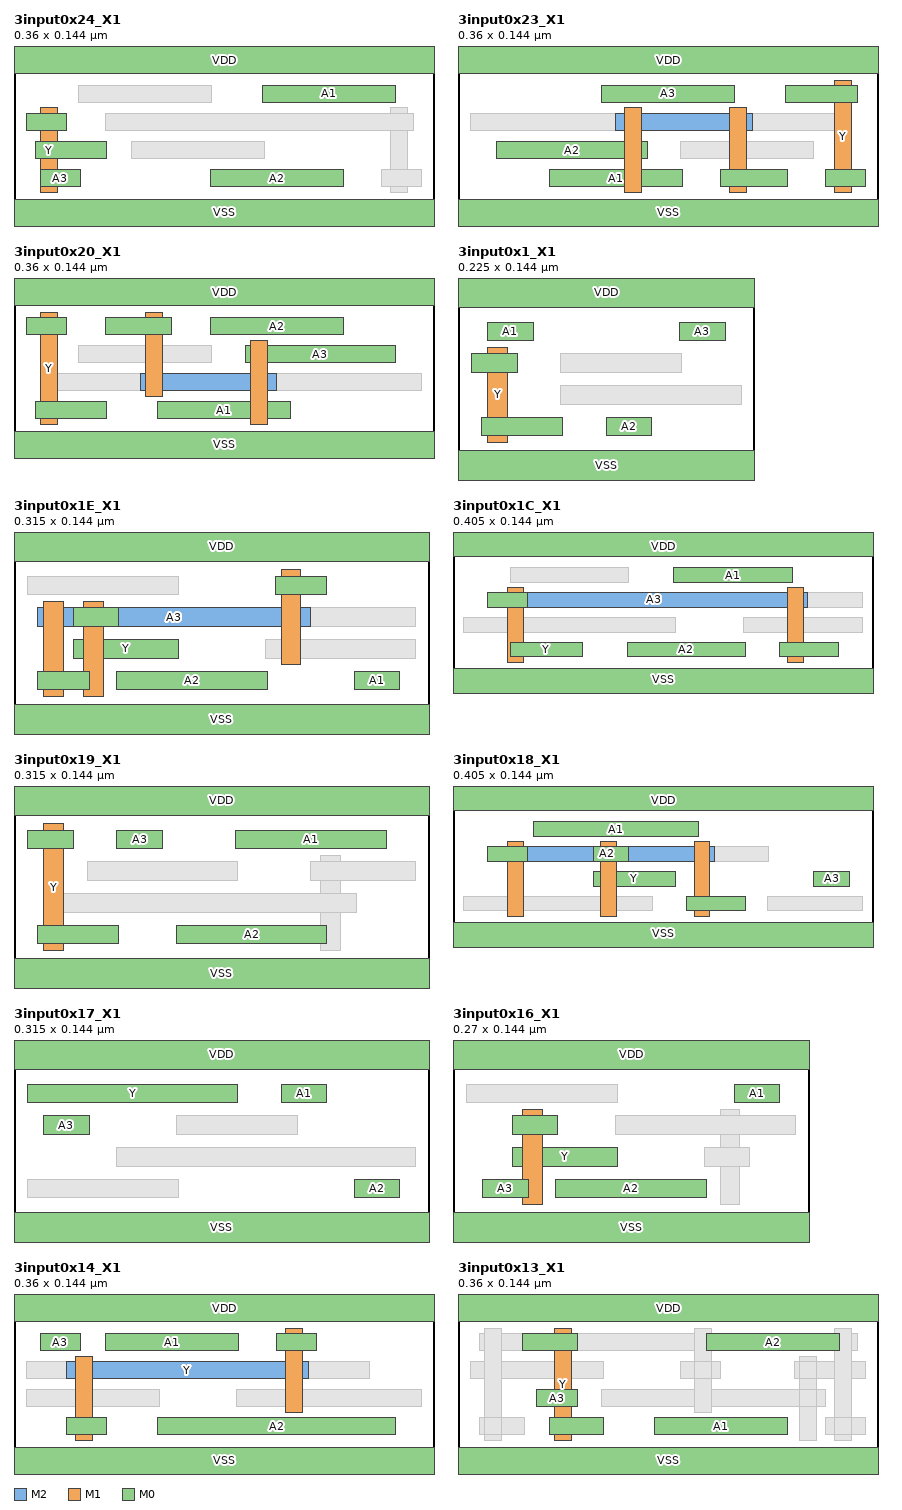
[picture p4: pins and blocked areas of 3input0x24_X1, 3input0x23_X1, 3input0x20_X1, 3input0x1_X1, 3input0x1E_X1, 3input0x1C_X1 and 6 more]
MACRO 3input0x24_X1
  CLASS CORE ;
  ORIGIN 0 0 ;
  FOREIGN 3input0x24_X1 0 0 ;
  SIZE 0.3600 BY 0.1440 ;
  SYMMETRY X Y ;
  SITE coresite ;
  PIN Y
    DIRECTION OUTPUT ;
    USE SIGNAL ;
    PORT
      LAYER M1 ;
        RECT 0.0225 0.0960 0.0375 0.0240 ;
      LAYER M0 ;
        RECT 0.0180 0.0670 0.0795 0.0530 ;
        RECT 0.0105 0.0910 0.0450 0.0770 ;
    END
  END Y
  PIN A3
    DIRECTION INPUT ;
    USE SIGNAL ;
    PORT
      LAYER M0 ;
        RECT 0.0225 0.0430 0.0570 0.0290 ;
    END
  END A3
  PIN A2
    DIRECTION INPUT ;
    USE SIGNAL ;
    PORT
      LAYER M0 ;
        RECT 0.1680 0.0430 0.2820 0.0290 ;
    END
  END A2
  PIN A1
    DIRECTION INPUT ;
    USE SIGNAL ;
    PORT
      LAYER M0 ;
        RECT 0.2130 0.1150 0.3270 0.1010 ;
    END
  END A1
  PIN VDD
    DIRECTION INOUT ;
    USE POWER ;
    SHAPE ABUTMENT ;
    PORT
      LAYER M0 ;
        RECT 0.0000 0.1260 0.3600 0.1620 ;
    END
  END VDD
  PIN VSS
    DIRECTION INOUT ;
    USE GROUND ;
    SHAPE ABUTMENT ;
    PORT
      LAYER M0 ;
        RECT 0.0000 -0.0180 0.3600 0.0180 ;
    END
  END VSS
  OBS
      LAYER V0 ;
        RECT 0.3230 0.0770 0.3370 0.0910 ;
        RECT 0.3230 0.0290 0.3370 0.0430 ;
        RECT 0.0230 0.0770 0.0370 0.0910 ;
        RECT 0.0230 0.0530 0.0370 0.0670 ;
      LAYER M1 ;
        RECT 0.3225 0.0960 0.3375 0.0240 ;
      LAYER M0 ;
        RECT 0.3150 0.0290 0.3495 0.0430 ;
        RECT 0.1005 0.0530 0.2145 0.0670 ;
        RECT 0.0780 0.0770 0.3420 0.0910 ;
        RECT 0.0555 0.1010 0.1695 0.1150 ;
  END
END 3input0x24_X1

MACRO 3input0x23_X1
  CLASS CORE ;
  ORIGIN 0 0 ;
  FOREIGN 3input0x23_X1 0 0 ;
  SIZE 0.3600 BY 0.1440 ;
  SYMMETRY X Y ;
  SITE coresite ;
  PIN Y
    DIRECTION OUTPUT ;
    USE SIGNAL ;
    PORT
      LAYER M1 ;
        RECT 0.3225 0.1200 0.3375 0.0240 ;
      LAYER M0 ;
        RECT 0.3150 0.0430 0.3495 0.0290 ;
        RECT 0.2805 0.1150 0.3420 0.1010 ;
    END
  END Y
  PIN A2
    DIRECTION INPUT ;
    USE SIGNAL ;
    PORT
      LAYER M2 ;
        RECT 0.1350 0.0910 0.2520 0.0770 ;
      LAYER M1 ;
        RECT 0.1425 0.0960 0.1575 0.0240 ;
        RECT 0.2325 0.0960 0.2475 0.0240 ;
      LAYER M0 ;
        RECT 0.0330 0.0670 0.1620 0.0530 ;
        RECT 0.2250 0.0430 0.2820 0.0290 ;
    END
  END A2
  PIN A1
    DIRECTION INPUT ;
    USE SIGNAL ;
    PORT
      LAYER M0 ;
        RECT 0.0780 0.0430 0.1920 0.0290 ;
    END
  END A1
  PIN A3
    DIRECTION INPUT ;
    USE SIGNAL ;
    PORT
      LAYER M0 ;
        RECT 0.1230 0.1150 0.2370 0.1010 ;
    END
  END A3
  PIN VDD
    DIRECTION INOUT ;
    USE POWER ;
    SHAPE ABUTMENT ;
    PORT
      LAYER M0 ;
        RECT 0.0000 0.1260 0.3600 0.1620 ;
    END
  END VDD
  PIN VSS
    DIRECTION INOUT ;
    USE GROUND ;
    SHAPE ABUTMENT ;
    PORT
      LAYER M0 ;
        RECT 0.0000 -0.0180 0.3600 0.0180 ;
    END
  END VSS
  OBS
      LAYER M0 ;
        RECT 0.1905 0.0530 0.3045 0.0670 ;
        RECT 0.0105 0.0770 0.3270 0.0910 ;
      LAYER V0 ;
        RECT 0.3230 0.1010 0.3370 0.1150 ;
        RECT 0.3230 0.0290 0.3370 0.0430 ;
        RECT 0.1430 0.0530 0.1570 0.0670 ;
        RECT 0.2330 0.0290 0.2470 0.0430 ;
      LAYER V1 ;
        RECT 0.1430 0.0770 0.1570 0.0910 ;
        RECT 0.2330 0.0770 0.2470 0.0910 ;
  END
END 3input0x23_X1

MACRO 3input0x20_X1
  CLASS CORE ;
  ORIGIN 0 0 ;
  FOREIGN 3input0x20_X1 0 0 ;
  SIZE 0.3600 BY 0.1440 ;
  SYMMETRY X Y ;
  SITE coresite ;
  PIN Y
    DIRECTION OUTPUT ;
    USE SIGNAL ;
    PORT
      LAYER M1 ;
        RECT 0.0225 0.1200 0.0375 0.0240 ;
      LAYER M0 ;
        RECT 0.0180 0.0430 0.0795 0.0290 ;
        RECT 0.0105 0.1150 0.0450 0.1010 ;
    END
  END Y
  PIN A3
    DIRECTION INPUT ;
    USE SIGNAL ;
    PORT
      LAYER M2 ;
        RECT 0.1080 0.0670 0.2250 0.0530 ;
      LAYER M1 ;
        RECT 0.2025 0.0960 0.2175 0.0240 ;
        RECT 0.1125 0.1200 0.1275 0.0480 ;
      LAYER M0 ;
        RECT 0.1980 0.0910 0.3270 0.0770 ;
        RECT 0.0780 0.1150 0.1350 0.1010 ;
    END
  END A3
  PIN A1
    DIRECTION INPUT ;
    USE SIGNAL ;
    PORT
      LAYER M0 ;
        RECT 0.1230 0.0430 0.2370 0.0290 ;
    END
  END A1
  PIN A2
    DIRECTION INPUT ;
    USE SIGNAL ;
    PORT
      LAYER M0 ;
        RECT 0.1680 0.1150 0.2820 0.1010 ;
    END
  END A2
  PIN VDD
    DIRECTION INOUT ;
    USE POWER ;
    SHAPE ABUTMENT ;
    PORT
      LAYER M0 ;
        RECT 0.0000 0.1260 0.3600 0.1620 ;
    END
  END VDD
  PIN VSS
    DIRECTION INOUT ;
    USE GROUND ;
    SHAPE ABUTMENT ;
    PORT
      LAYER M0 ;
        RECT 0.0000 -0.0180 0.3600 0.0180 ;
    END
  END VSS
  OBS
      LAYER M0 ;
        RECT 0.0330 0.0530 0.3495 0.0670 ;
        RECT 0.0555 0.0770 0.1695 0.0910 ;
      LAYER V0 ;
        RECT 0.0230 0.1010 0.0370 0.1150 ;
        RECT 0.0230 0.0290 0.0370 0.0430 ;
        RECT 0.1130 0.1010 0.1270 0.1150 ;
        RECT 0.2030 0.0770 0.2170 0.0910 ;
      LAYER V1 ;
        RECT 0.1130 0.0530 0.1270 0.0670 ;
        RECT 0.2030 0.0530 0.2170 0.0670 ;
  END
END 3input0x20_X1

MACRO 3input0x1_X1
  CLASS CORE ;
  ORIGIN 0 0 ;
  FOREIGN 3input0x1_X1 0 0 ;
  SIZE 0.2250 BY 0.1440 ;
  SYMMETRY X Y ;
  SITE coresite ;
  PIN Y
    DIRECTION OUTPUT ;
    USE SIGNAL ;
    PORT
      LAYER M1 ;
        RECT 0.0225 0.0960 0.0375 0.0240 ;
      LAYER M0 ;
        RECT 0.0180 0.0430 0.0795 0.0290 ;
        RECT 0.0105 0.0910 0.0450 0.0770 ;
    END
  END Y
  PIN A2
    DIRECTION INPUT ;
    USE SIGNAL ;
    PORT
      LAYER M0 ;
        RECT 0.1125 0.0430 0.1470 0.0290 ;
    END
  END A2
  PIN A1
    DIRECTION INPUT ;
    USE SIGNAL ;
    PORT
      LAYER M0 ;
        RECT 0.0225 0.1150 0.0570 0.1010 ;
    END
  END A1
  PIN A3
    DIRECTION INPUT ;
    USE SIGNAL ;
    PORT
      LAYER M0 ;
        RECT 0.1680 0.1150 0.2025 0.1010 ;
    END
  END A3
  PIN VDD
    DIRECTION INOUT ;
    USE POWER ;
    SHAPE ABUTMENT ;
    PORT
      LAYER M0 ;
        RECT 0.0000 0.1260 0.2250 0.1620 ;
    END
  END VDD
  PIN VSS
    DIRECTION INOUT ;
    USE GROUND ;
    SHAPE ABUTMENT ;
    PORT
      LAYER M0 ;
        RECT 0.0000 -0.0180 0.2250 0.0180 ;
    END
  END VSS
  OBS
      LAYER M0 ;
        RECT 0.0780 0.0530 0.2145 0.0670 ;
        RECT 0.0780 0.0770 0.1695 0.0910 ;
      LAYER V0 ;
        RECT 0.0230 0.0770 0.0370 0.0910 ;
        RECT 0.0230 0.0290 0.0370 0.0430 ;
  END
END 3input0x1_X1

MACRO 3input0x1E_X1
  CLASS CORE ;
  ORIGIN 0 0 ;
  FOREIGN 3input0x1E_X1 0 0 ;
  SIZE 0.3150 BY 0.1440 ;
  SYMMETRY X Y ;
  SITE coresite ;
  PIN Y
    DIRECTION OUTPUT ;
    USE SIGNAL ;
    PORT
      LAYER M1 ;
        RECT 0.0525 0.0960 0.0675 0.0240 ;
      LAYER M0 ;
        RECT 0.0450 0.0670 0.1245 0.0530 ;
        RECT 0.0450 0.0910 0.0795 0.0770 ;
    END
  END Y
  PIN A3
    DIRECTION INPUT ;
    USE SIGNAL ;
    PORT
      LAYER M2 ;
        RECT 0.0180 0.0910 0.2250 0.0770 ;
      LAYER M1 ;
        RECT 0.0225 0.0960 0.0375 0.0240 ;
        RECT 0.2025 0.1200 0.2175 0.0480 ;
      LAYER M0 ;
        RECT 0.0180 0.0430 0.0570 0.0290 ;
        RECT 0.1980 0.1150 0.2370 0.1010 ;
    END
  END A3
  PIN A2
    DIRECTION INPUT ;
    USE SIGNAL ;
    PORT
      LAYER M0 ;
        RECT 0.0780 0.0430 0.1920 0.0290 ;
    END
  END A2
  PIN A1
    DIRECTION INPUT ;
    USE SIGNAL ;
    PORT
      LAYER M0 ;
        RECT 0.2580 0.0430 0.2925 0.0290 ;
    END
  END A1
  PIN VDD
    DIRECTION INOUT ;
    USE POWER ;
    SHAPE ABUTMENT ;
    PORT
      LAYER M0 ;
        RECT 0.0000 0.1260 0.3150 0.1620 ;
    END
  END VDD
  PIN VSS
    DIRECTION INOUT ;
    USE GROUND ;
    SHAPE ABUTMENT ;
    PORT
      LAYER M0 ;
        RECT 0.0000 -0.0180 0.3150 0.0180 ;
    END
  END VSS
  OBS
      LAYER M0 ;
        RECT 0.1905 0.0530 0.3045 0.0670 ;
        RECT 0.1230 0.0770 0.3045 0.0910 ;
        RECT 0.0105 0.1010 0.1245 0.1150 ;
      LAYER V0 ;
        RECT 0.0530 0.0770 0.0670 0.0910 ;
        RECT 0.0530 0.0530 0.0670 0.0670 ;
        RECT 0.0230 0.0290 0.0370 0.0430 ;
        RECT 0.2030 0.1010 0.2170 0.1150 ;
      LAYER V1 ;
        RECT 0.0230 0.0770 0.0370 0.0910 ;
        RECT 0.2030 0.0770 0.2170 0.0910 ;
  END
END 3input0x1E_X1

MACRO 3input0x1C_X1
  CLASS CORE ;
  ORIGIN 0 0 ;
  FOREIGN 3input0x1C_X1 0 0 ;
  SIZE 0.4050 BY 0.1440 ;
  SYMMETRY X Y ;
  SITE coresite ;
  PIN A3
    DIRECTION INPUT ;
    USE SIGNAL ;
    PORT
      LAYER M2 ;
        RECT 0.0450 0.0910 0.3420 0.0770 ;
      LAYER M1 ;
        RECT 0.0525 0.0960 0.0675 0.0240 ;
        RECT 0.3225 0.0960 0.3375 0.0240 ;
      LAYER M0 ;
        RECT 0.0330 0.0910 0.0720 0.0770 ;
        RECT 0.3150 0.0430 0.3720 0.0290 ;
    END
  END A3
  PIN Y
    DIRECTION OUTPUT ;
    USE SIGNAL ;
    PORT
      LAYER M0 ;
        RECT 0.0555 0.0430 0.1245 0.0290 ;
    END
  END Y
  PIN A2
    DIRECTION INPUT ;
    USE SIGNAL ;
    PORT
      LAYER M0 ;
        RECT 0.1680 0.0430 0.2820 0.0290 ;
    END
  END A2
  PIN A1
    DIRECTION INPUT ;
    USE SIGNAL ;
    PORT
      LAYER M0 ;
        RECT 0.2130 0.1150 0.3270 0.1010 ;
    END
  END A1
  PIN VDD
    DIRECTION INOUT ;
    USE POWER ;
    SHAPE ABUTMENT ;
    PORT
      LAYER M0 ;
        RECT 0.0000 0.1260 0.4050 0.1620 ;
    END
  END VDD
  PIN VSS
    DIRECTION INOUT ;
    USE GROUND ;
    SHAPE ABUTMENT ;
    PORT
      LAYER M0 ;
        RECT 0.0000 -0.0180 0.4050 0.0180 ;
    END
  END VSS
  OBS
      LAYER M0 ;
        RECT 0.0105 0.0530 0.2145 0.0670 ;
        RECT 0.2805 0.0530 0.3945 0.0670 ;
        RECT 0.1230 0.0770 0.3945 0.0910 ;
        RECT 0.0555 0.1010 0.1695 0.1150 ;
      LAYER V0 ;
        RECT 0.0530 0.0770 0.0670 0.0910 ;
        RECT 0.3230 0.0290 0.3370 0.0430 ;
      LAYER V1 ;
        RECT 0.0530 0.0770 0.0670 0.0910 ;
        RECT 0.3230 0.0770 0.3370 0.0910 ;
  END
END 3input0x1C_X1

MACRO 3input0x19_X1
  CLASS CORE ;
  ORIGIN 0 0 ;
  FOREIGN 3input0x19_X1 0 0 ;
  SIZE 0.3150 BY 0.1440 ;
  SYMMETRY X Y ;
  SITE coresite ;
  PIN Y
    DIRECTION OUTPUT ;
    USE SIGNAL ;
    PORT
      LAYER M1 ;
        RECT 0.0225 0.1200 0.0375 0.0240 ;
      LAYER M0 ;
        RECT 0.0180 0.0430 0.0795 0.0290 ;
        RECT 0.0105 0.1150 0.0450 0.1010 ;
    END
  END Y
  PIN A2
    DIRECTION INPUT ;
    USE SIGNAL ;
    PORT
      LAYER M0 ;
        RECT 0.1230 0.0430 0.2370 0.0290 ;
    END
  END A2
  PIN A3
    DIRECTION INPUT ;
    USE SIGNAL ;
    PORT
      LAYER M0 ;
        RECT 0.0780 0.1150 0.1125 0.1010 ;
    END
  END A3
  PIN A1
    DIRECTION INPUT ;
    USE SIGNAL ;
    PORT
      LAYER M0 ;
        RECT 0.1680 0.1150 0.2820 0.1010 ;
    END
  END A1
  PIN VDD
    DIRECTION INOUT ;
    USE POWER ;
    SHAPE ABUTMENT ;
    PORT
      LAYER M0 ;
        RECT 0.0000 0.1260 0.3150 0.1620 ;
    END
  END VDD
  PIN VSS
    DIRECTION INOUT ;
    USE GROUND ;
    SHAPE ABUTMENT ;
    PORT
      LAYER M0 ;
        RECT 0.0000 -0.0180 0.3150 0.0180 ;
    END
  END VSS
  OBS
      LAYER V0 ;
        RECT 0.0230 0.1010 0.0370 0.1150 ;
        RECT 0.0230 0.0290 0.0370 0.0430 ;
        RECT 0.2330 0.0770 0.2470 0.0910 ;
        RECT 0.2330 0.0530 0.2470 0.0670 ;
      LAYER M1 ;
        RECT 0.2325 0.0960 0.2475 0.0240 ;
      LAYER M0 ;
        RECT 0.0330 0.0530 0.2595 0.0670 ;
        RECT 0.0555 0.0770 0.1695 0.0910 ;
        RECT 0.2250 0.0770 0.3045 0.0910 ;
  END
END 3input0x19_X1

MACRO 3input0x18_X1
  CLASS CORE ;
  ORIGIN 0 0 ;
  FOREIGN 3input0x18_X1 0 0 ;
  SIZE 0.4050 BY 0.1440 ;
  SYMMETRY X Y ;
  SITE coresite ;
  PIN Y
    DIRECTION OUTPUT ;
    USE SIGNAL ;
    PORT
      LAYER M1 ;
        RECT 0.1425 0.0960 0.1575 0.0240 ;
      LAYER M0 ;
        RECT 0.1350 0.0670 0.2145 0.0530 ;
        RECT 0.1350 0.0910 0.1695 0.0770 ;
    END
  END Y
  PIN A2
    DIRECTION INPUT ;
    USE SIGNAL ;
    PORT
      LAYER M2 ;
        RECT 0.0450 0.0910 0.2520 0.0770 ;
      LAYER M1 ;
        RECT 0.0525 0.0960 0.0675 0.0240 ;
        RECT 0.2325 0.0960 0.2475 0.0240 ;
      LAYER M0 ;
        RECT 0.0330 0.0910 0.0720 0.0770 ;
        RECT 0.2250 0.0430 0.2820 0.0290 ;
    END
  END A2
  PIN A3
    DIRECTION INPUT ;
    USE SIGNAL ;
    PORT
      LAYER M0 ;
        RECT 0.3480 0.0670 0.3825 0.0530 ;
    END
  END A3
  PIN A1
    DIRECTION INPUT ;
    USE SIGNAL ;
    PORT
      LAYER M0 ;
        RECT 0.0780 0.1150 0.2370 0.1010 ;
    END
  END A1
  PIN VDD
    DIRECTION INOUT ;
    USE POWER ;
    SHAPE ABUTMENT ;
    PORT
      LAYER M0 ;
        RECT 0.0000 0.1260 0.4050 0.1620 ;
    END
  END VDD
  PIN VSS
    DIRECTION INOUT ;
    USE GROUND ;
    SHAPE ABUTMENT ;
    PORT
      LAYER M0 ;
        RECT 0.0000 -0.0180 0.4050 0.0180 ;
    END
  END VSS
  OBS
      LAYER M0 ;
        RECT 0.0105 0.0290 0.1920 0.0430 ;
        RECT 0.3030 0.0290 0.3945 0.0430 ;
        RECT 0.1905 0.0770 0.3045 0.0910 ;
      LAYER V0 ;
        RECT 0.1430 0.0770 0.1570 0.0910 ;
        RECT 0.1430 0.0530 0.1570 0.0670 ;
        RECT 0.0530 0.0770 0.0670 0.0910 ;
        RECT 0.2330 0.0290 0.2470 0.0430 ;
      LAYER V1 ;
        RECT 0.0530 0.0770 0.0670 0.0910 ;
        RECT 0.2330 0.0770 0.2470 0.0910 ;
  END
END 3input0x18_X1

MACRO 3input0x17_X1
  CLASS CORE ;
  ORIGIN 0 0 ;
  FOREIGN 3input0x17_X1 0 0 ;
  SIZE 0.3150 BY 0.1440 ;
  SYMMETRY X Y ;
  SITE coresite ;
  PIN A2
    DIRECTION INPUT ;
    USE SIGNAL ;
    PORT
      LAYER M0 ;
        RECT 0.2580 0.0430 0.2925 0.0290 ;
    END
  END A2
  PIN A3
    DIRECTION INPUT ;
    USE SIGNAL ;
    PORT
      LAYER M0 ;
        RECT 0.0225 0.0910 0.0570 0.0770 ;
    END
  END A3
  PIN Y
    DIRECTION OUTPUT ;
    USE SIGNAL ;
    PORT
      LAYER M0 ;
        RECT 0.0105 0.1150 0.1695 0.1010 ;
    END
  END Y
  PIN A1
    DIRECTION INPUT ;
    USE SIGNAL ;
    PORT
      LAYER M0 ;
        RECT 0.2025 0.1150 0.2370 0.1010 ;
    END
  END A1
  PIN VDD
    DIRECTION INOUT ;
    USE POWER ;
    SHAPE ABUTMENT ;
    PORT
      LAYER M0 ;
        RECT 0.0000 0.1260 0.3150 0.1620 ;
    END
  END VDD
  PIN VSS
    DIRECTION INOUT ;
    USE GROUND ;
    SHAPE ABUTMENT ;
    PORT
      LAYER M0 ;
        RECT 0.0000 -0.0180 0.3150 0.0180 ;
    END
  END VSS
  OBS
      LAYER M0 ;
        RECT 0.0105 0.0290 0.1245 0.0430 ;
        RECT 0.0780 0.0530 0.3045 0.0670 ;
        RECT 0.1230 0.0770 0.2145 0.0910 ;
  END
END 3input0x17_X1

MACRO 3input0x16_X1
  CLASS CORE ;
  ORIGIN 0 0 ;
  FOREIGN 3input0x16_X1 0 0 ;
  SIZE 0.2700 BY 0.1440 ;
  SYMMETRY X Y ;
  SITE coresite ;
  PIN Y
    DIRECTION OUTPUT ;
    USE SIGNAL ;
    PORT
      LAYER M1 ;
        RECT 0.0525 0.0960 0.0675 0.0240 ;
      LAYER M0 ;
        RECT 0.0450 0.0670 0.1245 0.0530 ;
        RECT 0.0450 0.0910 0.0795 0.0770 ;
    END
  END Y
  PIN A3
    DIRECTION INPUT ;
    USE SIGNAL ;
    PORT
      LAYER M0 ;
        RECT 0.0225 0.0430 0.0570 0.0290 ;
    END
  END A3
  PIN A2
    DIRECTION INPUT ;
    USE SIGNAL ;
    PORT
      LAYER M0 ;
        RECT 0.0780 0.0430 0.1920 0.0290 ;
    END
  END A2
  PIN A1
    DIRECTION INPUT ;
    USE SIGNAL ;
    PORT
      LAYER M0 ;
        RECT 0.2130 0.1150 0.2475 0.1010 ;
    END
  END A1
  PIN VDD
    DIRECTION INOUT ;
    USE POWER ;
    SHAPE ABUTMENT ;
    PORT
      LAYER M0 ;
        RECT 0.0000 0.1260 0.2700 0.1620 ;
    END
  END VDD
  PIN VSS
    DIRECTION INOUT ;
    USE GROUND ;
    SHAPE ABUTMENT ;
    PORT
      LAYER M0 ;
        RECT 0.0000 -0.0180 0.2700 0.0180 ;
    END
  END VSS
  OBS
      LAYER V0 ;
        RECT 0.0530 0.0770 0.0670 0.0910 ;
        RECT 0.0530 0.0530 0.0670 0.0670 ;
        RECT 0.2030 0.0770 0.2170 0.0910 ;
        RECT 0.2030 0.0530 0.2170 0.0670 ;
      LAYER M1 ;
        RECT 0.2025 0.0960 0.2175 0.0240 ;
      LAYER M0 ;
        RECT 0.1905 0.0530 0.2250 0.0670 ;
        RECT 0.1230 0.0770 0.2595 0.0910 ;
        RECT 0.0105 0.1010 0.1245 0.1150 ;
  END
END 3input0x16_X1

MACRO 3input0x14_X1
  CLASS CORE ;
  ORIGIN 0 0 ;
  FOREIGN 3input0x14_X1 0 0 ;
  SIZE 0.3600 BY 0.1440 ;
  SYMMETRY X Y ;
  SITE coresite ;
  PIN Y
    DIRECTION OUTPUT ;
    USE SIGNAL ;
    PORT
      LAYER M2 ;
        RECT 0.0450 0.0910 0.2520 0.0770 ;
      LAYER M1 ;
        RECT 0.0525 0.0960 0.0675 0.0240 ;
        RECT 0.2325 0.1200 0.2475 0.0480 ;
      LAYER M0 ;
        RECT 0.0450 0.0430 0.0795 0.0290 ;
        RECT 0.2250 0.1150 0.2595 0.1010 ;
    END
  END Y
  PIN A2
    DIRECTION INPUT ;
    USE SIGNAL ;
    PORT
      LAYER M0 ;
        RECT 0.1230 0.0430 0.3270 0.0290 ;
    END
  END A2
  PIN A3
    DIRECTION INPUT ;
    USE SIGNAL ;
    PORT
      LAYER M0 ;
        RECT 0.0225 0.1150 0.0570 0.1010 ;
    END
  END A3
  PIN A1
    DIRECTION INPUT ;
    USE SIGNAL ;
    PORT
      LAYER M0 ;
        RECT 0.0780 0.1150 0.1920 0.1010 ;
    END
  END A1
  PIN VDD
    DIRECTION INOUT ;
    USE POWER ;
    SHAPE ABUTMENT ;
    PORT
      LAYER M0 ;
        RECT 0.0000 0.1260 0.3600 0.1620 ;
    END
  END VDD
  PIN VSS
    DIRECTION INOUT ;
    USE GROUND ;
    SHAPE ABUTMENT ;
    PORT
      LAYER M0 ;
        RECT 0.0000 -0.0180 0.3600 0.0180 ;
    END
  END VSS
  OBS
      LAYER M0 ;
        RECT 0.0105 0.0530 0.1245 0.0670 ;
        RECT 0.1905 0.0530 0.3495 0.0670 ;
        RECT 0.0105 0.0770 0.3045 0.0910 ;
      LAYER V0 ;
        RECT 0.0530 0.0290 0.0670 0.0430 ;
        RECT 0.2330 0.1010 0.2470 0.1150 ;
      LAYER V1 ;
        RECT 0.0530 0.0770 0.0670 0.0910 ;
        RECT 0.2330 0.0770 0.2470 0.0910 ;
  END
END 3input0x14_X1

MACRO 3input0x13_X1
  CLASS CORE ;
  ORIGIN 0 0 ;
  FOREIGN 3input0x13_X1 0 0 ;
  SIZE 0.3600 BY 0.1440 ;
  SYMMETRY X Y ;
  SITE coresite ;
  PIN Y
    DIRECTION OUTPUT ;
    USE SIGNAL ;
    PORT
      LAYER M1 ;
        RECT 0.0825 0.1200 0.0975 0.0240 ;
      LAYER M0 ;
        RECT 0.0780 0.0430 0.1245 0.0290 ;
        RECT 0.0555 0.1150 0.1020 0.1010 ;
    END
  END Y
  PIN A1
    DIRECTION INPUT ;
    USE SIGNAL ;
    PORT
      LAYER M0 ;
        RECT 0.1680 0.0430 0.2820 0.0290 ;
    END
  END A1
  PIN A3
    DIRECTION INPUT ;
    USE SIGNAL ;
    PORT
      LAYER M0 ;
        RECT 0.0675 0.0670 0.1020 0.0530 ;
    END
  END A3
  PIN A2
    DIRECTION INPUT ;
    USE SIGNAL ;
    PORT
      LAYER M0 ;
        RECT 0.2130 0.1150 0.3270 0.1010 ;
    END
  END A2
  PIN VDD
    DIRECTION INOUT ;
    USE POWER ;
    SHAPE ABUTMENT ;
    PORT
      LAYER M0 ;
        RECT 0.0000 0.1260 0.3600 0.1620 ;
    END
  END VDD
  PIN VSS
    DIRECTION INOUT ;
    USE GROUND ;
    SHAPE ABUTMENT ;
    PORT
      LAYER M0 ;
        RECT 0.0000 -0.0180 0.3600 0.0180 ;
    END
  END VSS
  OBS
      LAYER V1 ;
        RECT 0.0230 0.1010 0.0370 0.1150 ;
        RECT 0.2030 0.1010 0.2170 0.1150 ;
        RECT 0.3230 0.1010 0.3370 0.1150 ;
      LAYER M0 ;
        RECT 0.0180 0.0290 0.0570 0.0430 ;
        RECT 0.3150 0.0290 0.3495 0.0430 ;
        RECT 0.1230 0.0530 0.3150 0.0670 ;
        RECT 0.0105 0.0770 0.1245 0.0910 ;
        RECT 0.1905 0.0770 0.2250 0.0910 ;
        RECT 0.2880 0.0770 0.3495 0.0910 ;
      LAYER M2 ;
        RECT 0.0180 0.1010 0.3420 0.1150 ;
      LAYER M1 ;
        RECT 0.2925 0.0960 0.3075 0.0240 ;
        RECT 0.0225 0.1200 0.0375 0.0240 ;
        RECT 0.2025 0.1200 0.2175 0.0480 ;
        RECT 0.3225 0.1200 0.3375 0.0240 ;
      LAYER V0 ;
        RECT 0.2930 0.0770 0.3070 0.0910 ;
        RECT 0.2930 0.0530 0.3070 0.0670 ;
        RECT 0.0830 0.1010 0.0970 0.1150 ;
        RECT 0.0830 0.0290 0.0970 0.0430 ;
        RECT 0.0230 0.0290 0.0370 0.0430 ;
        RECT 0.2030 0.0770 0.2170 0.0910 ;
        RECT 0.3230 0.0290 0.3370 0.0430 ;
  END
END 3input0x13_X1

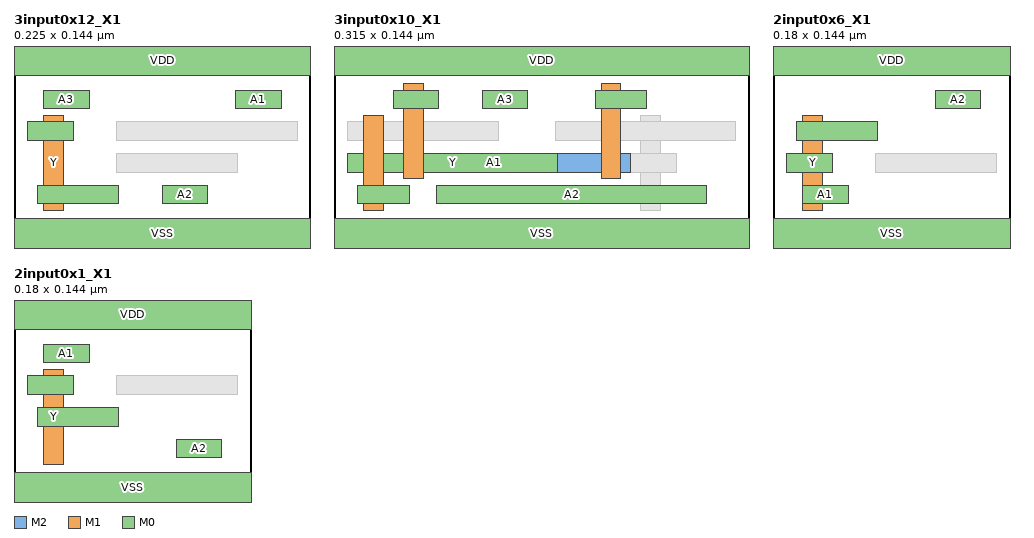
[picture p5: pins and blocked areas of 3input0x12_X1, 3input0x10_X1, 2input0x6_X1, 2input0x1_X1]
MACRO 3input0x12_X1
  CLASS CORE ;
  ORIGIN 0 0 ;
  FOREIGN 3input0x12_X1 0 0 ;
  SIZE 0.2250 BY 0.1440 ;
  SYMMETRY X Y ;
  SITE coresite ;
  PIN Y
    DIRECTION OUTPUT ;
    USE SIGNAL ;
    PORT
      LAYER M1 ;
        RECT 0.0225 0.0960 0.0375 0.0240 ;
      LAYER M0 ;
        RECT 0.0180 0.0430 0.0795 0.0290 ;
        RECT 0.0105 0.0910 0.0450 0.0770 ;
    END
  END Y
  PIN A2
    DIRECTION INPUT ;
    USE SIGNAL ;
    PORT
      LAYER M0 ;
        RECT 0.1125 0.0430 0.1470 0.0290 ;
    END
  END A2
  PIN A3
    DIRECTION INPUT ;
    USE SIGNAL ;
    PORT
      LAYER M0 ;
        RECT 0.0225 0.1150 0.0570 0.1010 ;
    END
  END A3
  PIN A1
    DIRECTION INPUT ;
    USE SIGNAL ;
    PORT
      LAYER M0 ;
        RECT 0.1680 0.1150 0.2025 0.1010 ;
    END
  END A1
  PIN VDD
    DIRECTION INOUT ;
    USE POWER ;
    SHAPE ABUTMENT ;
    PORT
      LAYER M0 ;
        RECT 0.0000 0.1260 0.2250 0.1620 ;
    END
  END VDD
  PIN VSS
    DIRECTION INOUT ;
    USE GROUND ;
    SHAPE ABUTMENT ;
    PORT
      LAYER M0 ;
        RECT 0.0000 -0.0180 0.2250 0.0180 ;
    END
  END VSS
  OBS
      LAYER M0 ;
        RECT 0.0780 0.0530 0.1695 0.0670 ;
        RECT 0.0780 0.0770 0.2145 0.0910 ;
      LAYER V0 ;
        RECT 0.0230 0.0770 0.0370 0.0910 ;
        RECT 0.0230 0.0290 0.0370 0.0430 ;
  END
END 3input0x12_X1

MACRO 3input0x10_X1
  CLASS CORE ;
  ORIGIN 0 0 ;
  FOREIGN 3input0x10_X1 0 0 ;
  SIZE 0.3150 BY 0.1440 ;
  SYMMETRY X Y ;
  SITE coresite ;
  PIN Y
    DIRECTION OUTPUT ;
    USE SIGNAL ;
    PORT
      LAYER M1 ;
        RECT 0.0525 0.1200 0.0675 0.0480 ;
      LAYER M0 ;
        RECT 0.0105 0.0670 0.1695 0.0530 ;
        RECT 0.0450 0.1150 0.0795 0.1010 ;
    END
  END Y
  PIN A1
    DIRECTION INPUT ;
    USE SIGNAL ;
    PORT
      LAYER M2 ;
        RECT 0.0180 0.0670 0.2250 0.0530 ;
      LAYER M1 ;
        RECT 0.0225 0.0960 0.0375 0.0240 ;
        RECT 0.2025 0.1200 0.2175 0.0480 ;
      LAYER M0 ;
        RECT 0.0180 0.0430 0.0570 0.0290 ;
        RECT 0.1980 0.1150 0.2370 0.1010 ;
    END
  END A1
  PIN A2
    DIRECTION INPUT ;
    USE SIGNAL ;
    PORT
      LAYER M0 ;
        RECT 0.0780 0.0430 0.2820 0.0290 ;
    END
  END A2
  PIN A3
    DIRECTION INPUT ;
    USE SIGNAL ;
    PORT
      LAYER M0 ;
        RECT 0.1125 0.1150 0.1470 0.1010 ;
    END
  END A3
  PIN VDD
    DIRECTION INOUT ;
    USE POWER ;
    SHAPE ABUTMENT ;
    PORT
      LAYER M0 ;
        RECT 0.0000 0.1260 0.3150 0.1620 ;
    END
  END VDD
  PIN VSS
    DIRECTION INOUT ;
    USE GROUND ;
    SHAPE ABUTMENT ;
    PORT
      LAYER M0 ;
        RECT 0.0000 -0.0180 0.3150 0.0180 ;
    END
  END VSS
  OBS
      LAYER V0 ;
        RECT 0.2330 0.0770 0.2470 0.0910 ;
        RECT 0.2330 0.0530 0.2470 0.0670 ;
        RECT 0.0530 0.1010 0.0670 0.1150 ;
        RECT 0.0530 0.0530 0.0670 0.0670 ;
        RECT 0.0230 0.0290 0.0370 0.0430 ;
        RECT 0.2030 0.1010 0.2170 0.1150 ;
      LAYER M1 ;
        RECT 0.2325 0.0960 0.2475 0.0240 ;
      LAYER M0 ;
        RECT 0.2250 0.0530 0.2595 0.0670 ;
        RECT 0.0105 0.0770 0.1245 0.0910 ;
        RECT 0.1680 0.0770 0.3045 0.0910 ;
      LAYER V1 ;
        RECT 0.0230 0.0530 0.0370 0.0670 ;
        RECT 0.2030 0.0530 0.2170 0.0670 ;
  END
END 3input0x10_X1

MACRO 2input0x6_X1
  CLASS CORE ;
  ORIGIN 0 0 ;
  FOREIGN 2input0x6_X1 0 0 ;
  SIZE 0.1800 BY 0.1440 ;
  SYMMETRY X Y ;
  SITE coresite ;
  PIN Y
    DIRECTION OUTPUT ;
    USE SIGNAL ;
    PORT
      LAYER M1 ;
        RECT 0.0225 0.0960 0.0375 0.0240 ;
      LAYER M0 ;
        RECT 0.0105 0.0670 0.0450 0.0530 ;
        RECT 0.0180 0.0910 0.0795 0.0770 ;
    END
  END Y
  PIN A1
    DIRECTION INPUT ;
    USE SIGNAL ;
    PORT
      LAYER M0 ;
        RECT 0.0225 0.0430 0.0570 0.0290 ;
    END
  END A1
  PIN A2
    DIRECTION INPUT ;
    USE SIGNAL ;
    PORT
      LAYER M0 ;
        RECT 0.1230 0.1150 0.1575 0.1010 ;
    END
  END A2
  PIN VDD
    DIRECTION INOUT ;
    USE POWER ;
    SHAPE ABUTMENT ;
    PORT
      LAYER M0 ;
        RECT 0.0000 0.1260 0.1800 0.1620 ;
    END
  END VDD
  PIN VSS
    DIRECTION INOUT ;
    USE GROUND ;
    SHAPE ABUTMENT ;
    PORT
      LAYER M0 ;
        RECT 0.0000 -0.0180 0.1800 0.0180 ;
    END
  END VSS
  OBS
      LAYER M0 ;
        RECT 0.0780 0.0530 0.1695 0.0670 ;
      LAYER V0 ;
        RECT 0.0230 0.0770 0.0370 0.0910 ;
        RECT 0.0230 0.0530 0.0370 0.0670 ;
  END
END 2input0x6_X1

MACRO 2input0x1_X1
  CLASS CORE ;
  ORIGIN 0 0 ;
  FOREIGN 2input0x1_X1 0 0 ;
  SIZE 0.1800 BY 0.1440 ;
  SYMMETRY X Y ;
  SITE coresite ;
  PIN Y
    DIRECTION OUTPUT ;
    USE SIGNAL ;
    PORT
      LAYER M1 ;
        RECT 0.0225 0.0960 0.0375 0.0240 ;
      LAYER M0 ;
        RECT 0.0180 0.0670 0.0795 0.0530 ;
        RECT 0.0105 0.0910 0.0450 0.0770 ;
    END
  END Y
  PIN A2
    DIRECTION INPUT ;
    USE SIGNAL ;
    PORT
      LAYER M0 ;
        RECT 0.1230 0.0430 0.1575 0.0290 ;
    END
  END A2
  PIN A1
    DIRECTION INPUT ;
    USE SIGNAL ;
    PORT
      LAYER M0 ;
        RECT 0.0225 0.1150 0.0570 0.1010 ;
    END
  END A1
  PIN VDD
    DIRECTION INOUT ;
    USE POWER ;
    SHAPE ABUTMENT ;
    PORT
      LAYER M0 ;
        RECT 0.0000 0.1260 0.1800 0.1620 ;
    END
  END VDD
  PIN VSS
    DIRECTION INOUT ;
    USE GROUND ;
    SHAPE ABUTMENT ;
    PORT
      LAYER M0 ;
        RECT 0.0000 -0.0180 0.1800 0.0180 ;
    END
  END VSS
  OBS
      LAYER M0 ;
        RECT 0.0780 0.0770 0.1695 0.0910 ;
      LAYER V0 ;
        RECT 0.0230 0.0770 0.0370 0.0910 ;
        RECT 0.0230 0.0530 0.0370 0.0670 ;
  END
END 2input0x1_X1

